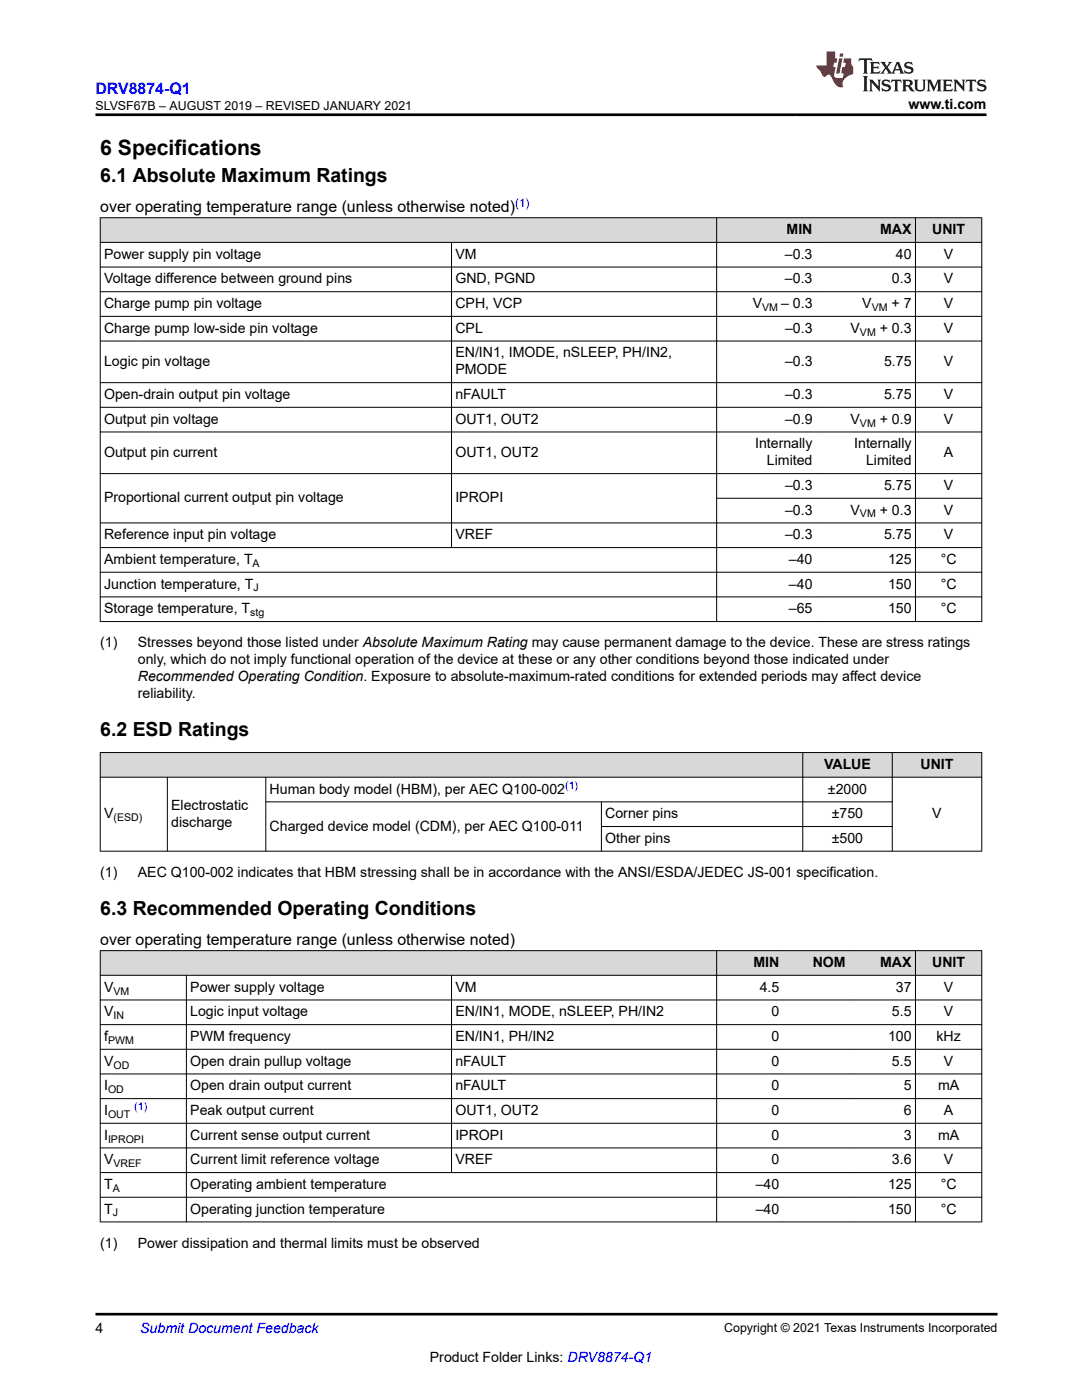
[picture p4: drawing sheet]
<svg xmlns="http://www.w3.org/2000/svg" width="216mm" height="279mm" viewBox="0 0 216 279" stroke-linecap="round" stroke-linejoin="round" font-family="sans-serif">
<defs><g id="words">
<text font-size="4.2" x="20" y="30.9">6 Specifications</text>
<g font-size="3.9">
<text x="20" y="36.3">6.1 Absolute Maximum Ratings</text>
<text x="20" y="146.9">6.2 ESD Ratings</text>
<text x="20" y="182.5">6.3 Recommended Operating Conditions</text>
</g>
<text font-size="3.2" fill="#00f" x="19.1" y="18.7">DRV8874-Q1</text>
<g font-size="3.2">
<text x="20" y="42.4">over operating temperature range (unless otherwise noted)</text>
<text x="20" y="188.7">over operating temperature range (unless otherwise noted)</text>
</g>
<g font-size="2.8">
<text x="181.3" y="21.8">www.ti.com</text>
<text x="157" y="46.7">MIN</text>
<text x="175.6" y="46.7">MAX</text>
<text x="186" y="46.7">UNIT</text>
<text x="20.8" y="51.6">Power supply pin voltage</text>
<text x="90.9" y="51.6">VM</text>
<text x="156.6" y="51.6">–0.3</text>
<text x="178.8" y="51.6">40</text>
<text x="188.3" y="51.6">V</text>
<text x="20.8" y="56.6">Voltage difference between ground pins</text>
<text x="90.9" y="56.6">GND, PGND</text>
<text x="156.6" y="56.6">–0.3</text>
<text x="178" y="56.6">0.3</text>
<text x="188.3" y="56.6">V</text>
<text x="20.8" y="61.5">Charge pump pin voltage</text>
<text x="90.9" y="61.5">CPH, VCP</text>
<text x="150.2" y="61.5">V</text>
<text x="155.9" y="61.5">– 0.3</text>
<text x="172.1" y="61.5">V</text>
<text x="177.9" y="61.5">+ 7</text>
<text x="188.3" y="61.5">V</text>
<text x="20.8" y="66.4">Charge pump low-side pin voltage</text>
<text x="90.9" y="66.4">CPL</text>
<text x="90.9" y="71.3">EN/IN1, IMODE, nSLEEP, PH/IN2,</text>
<text x="156.6" y="66.4">–0.3</text>
<text x="169.7" y="66.4">V</text>
<text x="175.6" y="66.4">+ 0.3</text>
<text x="188.3" y="66.4">V</text>
<text x="20.8" y="73">Logic pin voltage</text>
<text x="90.9" y="74.7">PMODE</text>
<text x="156.6" y="73">–0.3</text>
<text x="176.4" y="73">5.75</text>
<text x="188.3" y="73">V</text>
<text x="20.8" y="79.6">Open-drain output pin voltage</text>
<text x="90.9" y="79.6">nFAULT</text>
<text x="156.6" y="79.6">–0.3</text>
<text x="176.4" y="79.6">5.75</text>
<text x="188.3" y="79.6">V</text>
<text x="20.8" y="84.6">Output pin voltage</text>
<text x="90.9" y="84.6">OUT1, OUT2</text>
<text x="150.7" y="89.5">Internally</text>
<text x="156.6" y="84.6">–0.9</text>
<text x="169.7" y="84.6">V</text>
<text x="170.5" y="89.5">Internally</text>
<text x="175.6" y="84.6">+ 0.9</text>
<text x="188.3" y="84.6">V</text>
<text x="20.8" y="91.2">Output pin current</text>
<text x="90.9" y="91.2">OUT1, OUT2</text>
<text x="153" y="92.9">Limited</text>
<text x="172.8" y="92.9">Limited</text>
<text x="188.3" y="91.2">A</text>
<text x="20.8" y="100.3">Proportional current output pin voltage</text>
<text x="90.9" y="100.3">IPROPI</text>
<text x="156.6" y="97.8">–0.3</text>
<text x="176.4" y="97.8">5.75</text>
<text x="188.3" y="97.8">V</text>
<text x="20.8" y="107.6">Reference input pin voltage</text>
<text x="90.9" y="107.6">VREF</text>
<text x="156.6" y="102.7">–0.3</text>
<text x="156.6" y="107.6">–0.3</text>
<text x="169.7" y="102.7">V</text>
<text x="175.6" y="102.7">+ 0.3</text>
<text x="176.4" y="107.6">5.75</text>
<text x="188.3" y="102.7">V</text>
<text x="188.3" y="107.6">V</text>
<text x="20.8" y="112.6">Ambient temperature, T</text>
<text x="157.4" y="112.6">–40</text>
<text x="177.2" y="112.6">125</text>
<text x="187.7" y="112.6">°C</text>
<text x="20.8" y="117.5">Junction temperature, T</text>
<text x="157.4" y="117.5">–40</text>
<text x="177.2" y="117.5">150</text>
<text x="187.7" y="117.5">°C</text>
<text x="20.8" y="122.4">Storage temperature, T</text>
<text x="157.4" y="122.4">–65</text>
<text x="177.2" y="122.4">150</text>
<text x="187.7" y="122.4">°C</text>
<text x="20" y="129.2">(1)</text>
<text x="27.5" y="129.2">Stresses beyond those listed under Absolute Maximum Rating may cause permanent damage to the device. These are stress ratings</text>
<text x="27.5" y="132.6">only, which do not imply functional operation of the device at these or any other conditions beyond those indicated under</text>
<text x="27.5" y="136">Recommended Operating Condition. Exposure to absolute-maximum-rated conditions for extended periods may affect device</text>
<text x="27.5" y="139.4">reliability.</text>
<text x="164.4" y="153.5">VALUE</text>
<text x="183.7" y="153.5">UNIT</text>
<text x="34.2" y="161.6">Electrostatic</text>
<text x="53.8" y="158.4">Human body model (HBM), per AEC Q100-002</text>
<text x="165.2" y="158.4">±2000</text>
<text x="20.8" y="163.3">V</text>
<text x="34.2" y="165">discharge</text>
<text x="53.8" y="165.8">Charged device model (CDM), per AEC Q100-011</text>
<text x="120.8" y="163.3">Corner pins</text>
<text x="166" y="163.3">±750</text>
<text x="186" y="163.3">V</text>
<text x="120.8" y="168.2">Other pins</text>
<text x="166" y="168.2">±500</text>
<text x="20" y="175">(1)</text>
<text x="27.5" y="175">AEC Q100-002 indicates that HBM stressing shall be in accordance with the ANSI/ESDA/JEDEC JS-001 specification.</text>
<text x="20.8" y="197.9">V</text>
<text x="38" y="197.9">Power supply voltage</text>
<text x="90.9" y="197.9">VM</text>
<text x="150.3" y="193">MIN</text>
<text x="151.6" y="197.9">4.5</text>
<text x="162.2" y="193">NOM</text>
<text x="175.6" y="193">MAX</text>
<text x="178.8" y="197.9">37</text>
<text x="186" y="193">UNIT</text>
<text x="188.3" y="197.9">V</text>
<text x="20.8" y="202.8">V</text>
<text x="38" y="202.8">Logic input voltage</text>
<text x="90.9" y="202.8">EN/IN1, MODE, nSLEEP, PH/IN2</text>
<text x="153.9" y="202.8">0</text>
<text x="178" y="202.8">5.5</text>
<text x="188.3" y="202.8">V</text>
<text x="20.8" y="207.8">f</text>
<text x="38" y="207.8">PWM frequency</text>
<text x="90.9" y="207.8">EN/IN1, PH/IN2</text>
<text x="153.9" y="207.8">0</text>
<text x="177.2" y="207.8">100</text>
<text x="186.9" y="207.8">kHz</text>
<text x="20.8" y="212.7">V</text>
<text x="38" y="212.7">Open drain pullup voltage</text>
<text x="90.9" y="212.7">nFAULT</text>
<text x="153.9" y="212.7">0</text>
<text x="178" y="212.7">5.5</text>
<text x="188.3" y="212.7">V</text>
<text x="20.8" y="217.6">I</text>
<text x="38" y="217.6">Open drain output current</text>
<text x="90.9" y="217.6">nFAULT</text>
<text x="153.9" y="217.6">0</text>
<text x="180.3" y="217.6">5</text>
<text x="187.2" y="217.6">mA</text>
<text x="20.8" y="222.5">I</text>
<text x="20.8" y="227.4">I</text>
<text x="38" y="227.4">Current sense output current</text>
<text x="38" y="222.5">Peak output current</text>
<text x="90.9" y="227.4">IPROPI</text>
<text x="90.9" y="222.5">OUT1, OUT2</text>
<text x="153.9" y="222.5">0</text>
<text x="153.9" y="227.4">0</text>
<text x="180.3" y="222.5">6</text>
<text x="180.3" y="227.4">3</text>
<text x="187.2" y="227.4">mA</text>
<text x="188.3" y="222.5">A</text>
<text x="20.8" y="232.4">V</text>
<text x="38" y="232.4">Current limit reference voltage</text>
<text x="90.9" y="232.4">VREF</text>
<text x="153.9" y="232.4">0</text>
<text x="178" y="232.4">3.6</text>
<text x="188.3" y="232.4">V</text>
<text x="20.8" y="237.3">T</text>
<text x="38" y="237.3">Operating ambient temperature</text>
<text x="150.8" y="237.3">–40</text>
<text x="177.2" y="237.3">125</text>
<text x="187.7" y="237.3">°C</text>
<text x="20.8" y="242.2">T</text>
<text x="38" y="242.2">Operating junction temperature</text>
<text x="150.8" y="242.2">–40</text>
<text x="177.2" y="242.2">150</text>
<text x="187.7" y="242.2">°C</text>
<text x="20" y="249">(1)</text>
<text x="27.5" y="249">Power dissipation and thermal limits must be observed</text>
<text x="19.1" y="266.1">4</text>
<text x="85.8" y="271.7">Product Folder Links: DRV8874-Q1</text>
</g>
<text font-size="2.8" fill="#00f" x="28" y="266.1">Submit Document Feedback</text>
<g font-size="2.5">
<text x="19" y="21.9">SLVSF67B – AUGUST 2019 – REVISED JANUARY 2021</text>
<text x="144.5" y="265.8">Copyright © 2021 Texas Instruments Incorporated</text>
</g>
<text font-size="2.4" fill="#00f" x="102.8" y="41.3">(1)</text>
<g font-size="2.1">
<text x="152.1" y="62.1">VM</text>
<text x="173.9" y="62.1">VM</text>
<text x="171.6" y="67">VM</text>
<text x="171.6" y="85.1">VM</text>
<text x="171.6" y="103.3">VM</text>
<text x="50.4" y="113.1">A</text>
<text x="50.6" y="118">J</text>
<text x="49.9" y="123">stg</text>
<text x="22.6" y="163.9">(ESD)</text>
<text x="22.6" y="203.4">IN</text>
<text x="22.6" y="198.5">VM</text>
<text x="21.6" y="208.3">PWM</text>
<text x="22.6" y="213.2">OD</text>
<text x="21.6" y="218.2">OD</text>
<text x="21.6" y="223.1">OUT</text>
<text x="21.6" y="228">IPROPI</text>
<text x="22.7" y="232.9">VREF</text>
<text x="22.5" y="237.9">A</text>
<text x="22.5" y="242.8">J</text>
</g>
<g font-size="2.1" fill="#00f">
<text x="112.8" y="157.4">(1)</text>
<text x="26.8" y="221.6">(1)</text>
</g>
</g></defs>
<g fill="#d8d8d8">
<path d="M20 43.5h175.9v4.9h-175.9z" fill-rule="evenodd"/>
<path d="M20.1 43.5h122.8v4.8h-122.8z" fill-rule="evenodd"/>
<path d="M143.1 43.5h19.7v4.8h-19.7z" fill-rule="evenodd"/>
<path d="M162.8 43.5h19.8v4.8h-19.8z" fill-rule="evenodd"/>
<path d="M182.7 43.5h13.1v4.8h-13.1z" fill-rule="evenodd"/>
</g>
<g fill="none" stroke="#000" stroke-width=".2">
<path d="M19.9 43.5h176.1M19.9 48.4h176.1M19.9 53.3h176.1M19.9 58.2h176.1M20 43.4v80.7M90.1 48.3v61M143 43.4v80.7M182.7 43.4v80.7M195.9 43.4v80.7M19.9 63.1h176.1M19.9 68.1h176.1M19.9 76.4h176.1"/>
<path d="M19.9 81.3h176.1M19.9 86.2h176.1M19.9 94.5h176.1M142.9 99.4h53.1M19.9 104.4h176.1M19.9 109.3h176.1M19.9 114.2h176.1M19.9 119.1h176.1M19.9 124h176.1"/>
</g>
<g fill="#d8d8d8">
<path d="M20 150.2h175.9v4.9h-175.9z" fill-rule="evenodd"/>
<path d="M20.1 150.2h140v4.8h-140z" fill-rule="evenodd"/>
<path d="M160.2 150.2h17.8v4.8h-17.8z" fill-rule="evenodd"/>
<path d="M178.1 150.2h17.7v4.8h-17.7z" fill-rule="evenodd"/>
</g>
<path d="M19.9 150.2h176.1M19.9 155.1h176.1M20 150.1v19.8M33.4 155v14.9M53 155v14.9M120 160v9.9M160.2 150.1v19.8M178 150.1v19.8M195.9 150.1v19.8M19.9 169.9h176.1M53 160h125.1M119.9 165h58.2" fill="none" stroke="#000" stroke-width=".2"/>
<g fill="#d8d8d8">
<path d="M20 189.7h175.9v4.9h-175.9z" fill-rule="evenodd"/>
<path d="M20.1 189.8h122.8v4.8h-122.8z" fill-rule="evenodd"/>
<path d="M143.1 189.8h13.1v4.8h-13.1z" fill-rule="evenodd"/>
<path d="M156.2 189.8h13.2v4.8h-13.2z" fill-rule="evenodd"/>
<path d="M169.4 189.8h13.2v4.8h-13.2z" fill-rule="evenodd"/>
<path d="M182.7 189.8h13.1v4.8h-13.1z" fill-rule="evenodd"/>
</g>
<g fill="none" stroke="#000" stroke-width=".2">
<path d="M19.9 189.7h176.1M19.9 194.6h176.1M19.9 199.6h176.1M20 189.7v54.2M37.2 194.6v49.3M90.1 194.6v39.5M143 189.7v54.2M182.7 189.7v54.2M195.9 189.7v54.2M19.9 204.5h176.1M19.9 209.4h176.1M19.9 214.3h176.1"/>
<path d="M19.9 219.3h176.1M19.9 224.2h176.1M19.9 229.1h176.1M19.9 234h176.1M19.9 238.9h176.1M19.9 243.9h176.1"/>
</g>
<path d="M171.5 11.6l-.2 .6 .5-.2h.6v.1v2.2l-.2 .4h1l-.2-.4v-2.2v-.1h.5l.6 .2-.2-.6zM173.6 12.4l.2 .3v1.6l-.2 .4h1.9l.1-.6a1.08 1.08 0 0 1-1.3 .2v-.7h.6l.4 .2v-.7l-.4 .2h-.6v-.5l.2-.2a1 1 0 0 1 1 .3l-.1-.5zM175.7 12.4l.9 1.1-1 1.2h.9l-.2-.2 .5-.8 .4 .8-.2 .2h1.6l-.2-.2 .2-.5h.9l.1 .5-.1 .2h.9l-.2-.4-.8-1.9h-.5l-.9 2.1-.9-1.1 .9-1h-.8l.2 .2-.4 .6-.4-.6 .2-.2zM179 12.8l.4 1h-.7zM180.7 12.5a.65 .65 0 0 0-.2 .7 .65 .65 0 0 0 .6 .5l.6 .1 .1 .3a.79 .79 0 0 1-.7 .4 .79 .79 0 0 1-.7-.5l.1 .7 .2-.1a.93 .93 0 0 0 1.1 0 .93 .93 0 0 0 .4-.9 1.46 1.46 0 0 0-1.2-.6l-.1-.3a1.09 1.09 0 0 1 1.2 .2l-.2-.6-.1 .1-.5-.2zM172.2 15.2l.2 .4v2.2l-.2 .4h1l-.2-.4v-2.2l.2-.4zM173.4 15.9l.2 .4v1.5l-.2 .4h.8l-.3-.4 .1-1.3 1.6 1.8v-2l.2-.4h-.7l.1 .2 .1 1.1-1.2-1.3zM176.2 16a.65 .65 0 0 0-.2 .8 .65 .65 0 0 0 .6 .4l.6 .2 .1 .2a.79 .79 0 0 1-.7 .4 .79 .79 0 0 1-.7-.5l.1 .7 .2-.1a.93 .93 0 0 0 1.1 .1 .93 .93 0 0 0 .4-1 1.46 1.46 0 0 0-1.2-.5l-.1-.4a1.09 1.09 0 0 1 1.2 .2l-.1-.6-.2 .1-.5-.1zM177.9 15.9l-.1 .6a.63 .63 0 0 1 .8-.3v1.6l-.3 .4h1l-.2-.4v-1.6a.66 .66 0 0 1 .8 .3l-.1-.6zM180 15.9l.2 .4v1.5l-.2 .4h1l-.2-.2-.1-.7h.5l.1 .2a.79 .79 0 0 0 1.2 .6l-1-.9a.61 .61 0 0 0 .6-.6 .61 .61 0 0 0-.5-.7zM180.8 16.2h.1a.47 .47 0 0 1 .5 .1 .47 .47 0 0 1 .1 .5l-.1 .1-.7 .1zM182.3 15.9l.2 .2a2.27 2.27 0 0 0 .4 2 1.04 1.04 0 0 0 1.7-.7v-1.3l.2-.2h-.8l.2 .4v1.1a.6 .6 0 0 1-.6 .6 .6 .6 0 0 1-.6-.6v-1.1l.3-.4zM184.9 15.9l.2 .4v1.5l-.2 .4h.8l-.3-.4v-1.4l.9 1.9 .9-1.9v1.4l-.3 .4h1l-.2-.4v-1.5l.2-.4h-.8l-.7 1.5-.6-1.5zM188.1 15.9l.2 .4v1.5l-.2 .4h1.9l.1-.6a1.09 1.09 0 0 1-1.3 .2v-.7h.6l.4 .2v-.6l-.4 .2h-.6v-.6l.2-.1a1.01 1.01 0 0 1 1 .3l-.1-.6zM190.2 15.9l.3 .4v1.5l-.3 .4h.8l-.2-.4v-1.3l1.6 1.8v-2l.2-.4h-.7l.2 .2v1.1l-1.2-1.3zM192.8 15.9l-.1 .6a.63 .63 0 0 1 .8-.3v1.6l-.3 .4h1l-.2-.4v-1.6a.66 .66 0 0 1 .8 .3l-.1-.6zM195.2 16a.65 .65 0 0 0-.2 .8 .65 .65 0 0 0 .6 .4l.6 .2 .2 .2a.79 .79 0 0 1-.7 .4 .79 .79 0 0 1-.7-.5l.1 .7 .2-.1a.93 .93 0 0 0 1 .1 .93 .93 0 0 0 .5-1 1.46 1.46 0 0 0-1.3-.5v-.4a1.09 1.09 0 0 1 1.2 .2l-.2-.6-.2 .1-.5-.1z" fill="#231f20"/>
<path d="M164.9 10.3v2.7h-2l.1 .4 .8 1a.95 .95 0 0 0 1 .9 .59 .59 0 0 1 .5-.4 .59 .59 0 0 1 .5 .3l.4 .8a1.59 1.59 0 0 0 2.1 1.4 1.61 1.61 0 0 1 1-2.3l1-.3-.1-1.5a1.59 1.59 0 0 1-.3-1.7h-1.5l-.2 .9h.6l-.2 .9h-.5l-.2 .9v.3l.4 .1-.1 .9h-.7a.73 .73 0 0 1-1-.7l.3-1.5h-.5l.1-.9h.5l.2-.9h-.5v-1.3zM167.4 11.6l-.6 3.1h.7l.6-3.1zM167.6 10.7l-.1 .6h.7l.1-.6z" fill="#ed1c24"/>
<path d="M19.1 22.9h177.8M19.1 262.3h180" fill="none" stroke="#000" stroke-width=".53"/>
<use href="#words"/>
</svg>
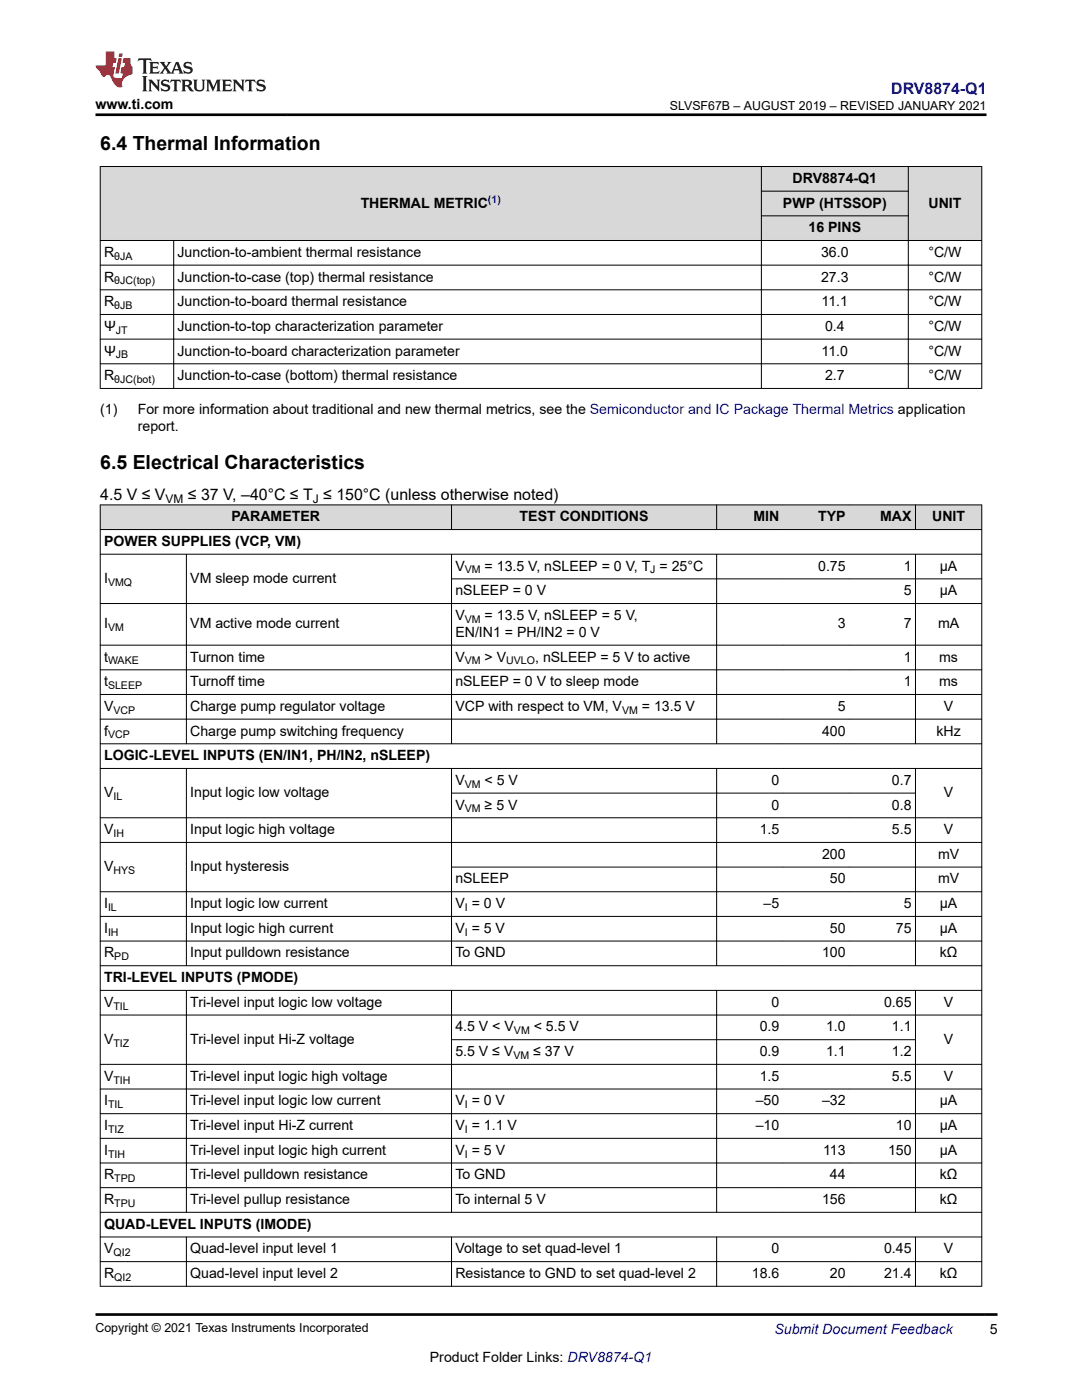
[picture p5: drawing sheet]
<svg xmlns="http://www.w3.org/2000/svg" width="216mm" height="279mm" viewBox="0 0 216 279" stroke-linecap="round" stroke-linejoin="round" font-family="sans-serif">
<defs><g id="words">
<g font-size="3.9">
<text x="20" y="29.9">6.4 Thermal Information</text>
<text x="20" y="93.6">6.5 Electrical Characteristics</text>
</g>
<text font-size="3.2" fill="#00f" x="177.8" y="18.7">DRV8874-Q1</text>
<g font-size="3.2">
<text x="20" y="99.7">4.5 V ≤ V</text>
<text x="37.5" y="99.7">≤ 37 V, –40°C ≤ T ≤ 150°C (unless otherwise noted)</text>
</g>
<g font-size="2.8">
<text x="19.1" y="21.8">www.ti.com</text>
<text x="72" y="41.4">THERMAL METRIC</text>
<text x="156.2" y="41.4">PWP (HTSSOP)</text>
<text x="158.1" y="36.5">DRV8874-Q1</text>
<text x="185.3" y="41.4">UNIT</text>
<text x="161.3" y="46.3">16 PINS</text>
<text x="20.8" y="51.3">R</text>
<text x="35.4" y="51.3">Junction-to-ambient thermal resistance</text>
<text x="163.8" y="51.3">36.0</text>
<text x="185.3" y="51.3">°C/W</text>
<text x="20.8" y="56.2">R</text>
<text x="35.4" y="56.2">Junction-to-case (top) thermal resistance</text>
<text x="163.8" y="56.2">27.3</text>
<text x="185.3" y="56.2">°C/W</text>
<text x="20.8" y="61.1">R</text>
<text x="35.4" y="61.1">Junction-to-board thermal resistance</text>
<text x="163.9" y="61.1">11.1</text>
<text x="185.3" y="61.1">°C/W</text>
<text x="20.8" y="66">Ψ</text>
<text x="20.8" y="71">Ψ</text>
<text x="35.4" y="66">Junction-to-top characterization parameter</text>
<text x="35.4" y="71">Junction-to-board characterization parameter</text>
<text x="163.9" y="71">11.0</text>
<text x="164.6" y="66">0.4</text>
<text x="185.3" y="66">°C/W</text>
<text x="185.3" y="71">°C/W</text>
<text x="20.8" y="75.9">R</text>
<text x="35.4" y="75.9">Junction-to-case (bottom) thermal resistance</text>
<text x="164.6" y="75.9">2.7</text>
<text x="185.3" y="75.9">°C/W</text>
<text x="20" y="82.7">(1)</text>
<text x="27.5" y="82.7">For more information about traditional and new thermal metrics, see the Semiconductor and IC Package Thermal Metrics application</text>
<text x="27.5" y="86.1">report.</text>
<text x="46.2" y="104">PARAMETER</text>
<text x="103.7" y="104">TEST CONDITIONS</text>
<text x="150.3" y="104">MIN</text>
<text x="163.3" y="104">TYP</text>
<text x="175.6" y="104">MAX</text>
<text x="186" y="104">UNIT</text>
<text x="20.8" y="109">POWER SUPPLIES (VCP, VM)</text>
<text x="90.9" y="113.9">V</text>
<text x="96.7" y="113.9">= 13.5 V, nSLEEP = 0 V, T = 25°C</text>
<text x="163.3" y="113.9">0.75</text>
<text x="180.3" y="113.9">1</text>
<text x="187.5" y="113.9">µA</text>
<text x="20.8" y="116.3">I</text>
<text x="38" y="116.3">VM sleep mode current</text>
<text x="90.9" y="118.8">nSLEEP = 0 V</text>
<text x="180.3" y="118.8">5</text>
<text x="187.5" y="118.8">µA</text>
<text x="20.8" y="125.4">I</text>
<text x="38" y="125.4">VM active mode current</text>
<text x="90.9" y="123.7">V</text>
<text x="96.7" y="123.7">= 13.5 V, nSLEEP = 5 V,</text>
<text x="167.2" y="125.4">3</text>
<text x="180.3" y="125.4">7</text>
<text x="187.2" y="125.4">mA</text>
<text x="90.9" y="127.1">EN/IN1 = PH/IN2 = 0 V</text>
<text x="20.8" y="136.9">t</text>
<text x="20.8" y="132">t</text>
<text x="38" y="136.9">Turnoff time</text>
<text x="38" y="132">Turnon time</text>
<text x="90.9" y="136.9">nSLEEP = 0 V to sleep mode</text>
<text x="90.9" y="132">V</text>
<text x="96.7" y="132">&gt; V</text>
<text x="106.8" y="132">, nSLEEP = 5 V to active</text>
<text x="180.3" y="132">1</text>
<text x="180.3" y="136.9">1</text>
<text x="187.4" y="132">ms</text>
<text x="187.4" y="136.9">ms</text>
<text x="20.8" y="141.9">V</text>
<text x="38" y="141.9">Charge pump regulator voltage</text>
<text x="90.9" y="141.9">VCP with respect to VM, V</text>
<text x="128.1" y="141.9">= 13.5 V</text>
<text x="167.2" y="141.9">5</text>
<text x="188.3" y="141.9">V</text>
<text x="20.8" y="146.8">f</text>
<text x="38" y="146.8">Charge pump switching frequency</text>
<text x="164" y="146.8">400</text>
<text x="186.9" y="146.8">kHz</text>
<text x="20.8" y="151.7">LOGIC-LEVEL INPUTS (EN/IN1, PH/IN2, nSLEEP)</text>
<text x="20.8" y="159.1">V</text>
<text x="38" y="159.1">Input logic low voltage</text>
<text x="90.9" y="161.6">V</text>
<text x="90.9" y="156.6">V</text>
<text x="96.7" y="156.6">&lt; 5 V</text>
<text x="96.7" y="161.6">≥ 5 V</text>
<text x="153.9" y="156.6">0</text>
<text x="153.9" y="161.6">0</text>
<text x="178" y="156.6">0.7</text>
<text x="178" y="161.6">0.8</text>
<text x="188.3" y="159.1">V</text>
<text x="20.8" y="166.5">V</text>
<text x="38" y="166.5">Input logic high voltage</text>
<text x="151.6" y="166.5">1.5</text>
<text x="178" y="166.5">5.5</text>
<text x="188.3" y="166.5">V</text>
<text x="20.8" y="173.9">V</text>
<text x="38" y="173.9">Input hysteresis</text>
<text x="164" y="171.4">200</text>
<text x="187.2" y="171.4">mV</text>
<text x="90.9" y="176.3">nSLEEP</text>
<text x="165.6" y="176.3">50</text>
<text x="187.2" y="176.3">mV</text>
<text x="20.8" y="181.2">I</text>
<text x="38" y="181.2">Input logic low current</text>
<text x="90.9" y="181.2">V = 0 V</text>
<text x="152.4" y="181.2">–5</text>
<text x="180.3" y="181.2">5</text>
<text x="187.5" y="181.2">µA</text>
<text x="20.8" y="186.2">I</text>
<text x="20.8" y="191.1">R</text>
<text x="38" y="186.2">Input logic high current</text>
<text x="38" y="191.1">Input pulldown resistance</text>
<text x="90.9" y="186.2">V = 5 V</text>
<text x="90.9" y="191.1">To GND</text>
<text x="164" y="191.1">100</text>
<text x="165.6" y="186.2">50</text>
<text x="178.8" y="186.2">75</text>
<text x="187.5" y="191.1">kΩ</text>
<text x="187.5" y="186.2">µA</text>
<text x="20.8" y="196">TRI-LEVEL INPUTS (PMODE)</text>
<text x="20.8" y="200.9">V</text>
<text x="38" y="200.9">Tri-level input logic low voltage</text>
<text x="153.9" y="200.9">0</text>
<text x="176.4" y="200.9">0.65</text>
<text x="188.3" y="200.9">V</text>
<text x="20.8" y="208.3">V</text>
<text x="38" y="208.3">Tri-level input Hi-Z voltage</text>
<text x="90.9" y="205.8">4.5 V &lt; V</text>
<text x="106.5" y="205.8">&lt; 5.5 V</text>
<text x="151.6" y="205.8">0.9</text>
<text x="164.8" y="205.8">1.0</text>
<text x="178" y="205.8">1.1</text>
<text x="188.3" y="208.3">V</text>
<text x="20.8" y="215.7">V</text>
<text x="38" y="215.7">Tri-level input logic high voltage</text>
<text x="90.9" y="210.8">5.5 V ≤ V</text>
<text x="106.4" y="210.8">≤ 37 V</text>
<text x="151.6" y="215.7">1.5</text>
<text x="151.6" y="210.8">0.9</text>
<text x="164.8" y="210.8">1.1</text>
<text x="178" y="215.7">5.5</text>
<text x="178" y="210.8">1.2</text>
<text x="188.3" y="215.7">V</text>
<text x="20.8" y="220.6">I</text>
<text x="38" y="220.6">Tri-level input logic low current</text>
<text x="90.9" y="220.6">V = 0 V</text>
<text x="150.8" y="220.6">–50</text>
<text x="164" y="220.6">–32</text>
<text x="187.5" y="220.6">µA</text>
<text x="20.8" y="225.5">I</text>
<text x="38" y="225.5">Tri-level input Hi-Z current</text>
<text x="90.9" y="225.5">V = 1.1 V</text>
<text x="150.8" y="225.5">–10</text>
<text x="178.8" y="225.5">10</text>
<text x="187.5" y="225.5">µA</text>
<text x="20.8" y="230.5">I</text>
<text x="38" y="230.5">Tri-level input logic high current</text>
<text x="90.9" y="230.5">V = 5 V</text>
<text x="164.2" y="230.5">113</text>
<text x="177.2" y="230.5">150</text>
<text x="187.5" y="230.5">µA</text>
<text x="20.8" y="235.4">R</text>
<text x="38" y="235.4">Tri-level pulldown resistance</text>
<text x="90.9" y="235.4">To GND</text>
<text x="165.6" y="235.4">44</text>
<text x="187.5" y="235.4">kΩ</text>
<text x="20.8" y="240.3">R</text>
<text x="20.8" y="245.2">QUAD-LEVEL INPUTS (IMODE)</text>
<text x="38" y="240.3">Tri-level pullup resistance</text>
<text x="90.9" y="240.3">To internal 5 V</text>
<text x="164" y="240.3">156</text>
<text x="187.5" y="240.3">kΩ</text>
<text x="20.8" y="250.1">V</text>
<text x="38" y="250.1">Quad-level input level 1</text>
<text x="90.9" y="250.1">Voltage to set quad-level 1</text>
<text x="153.9" y="250.1">0</text>
<text x="176.4" y="250.1">0.45</text>
<text x="188.3" y="250.1">V</text>
<text x="20.8" y="255.1">R</text>
<text x="38" y="255.1">Quad-level input level 2</text>
<text x="90.9" y="255.1">Resistance to GND to set quad-level 2</text>
<text x="150" y="255.1">18.6</text>
<text x="165.6" y="255.1">20</text>
<text x="176.4" y="255.1">21.4</text>
<text x="187.5" y="255.1">kΩ</text>
<text x="197.5" y="266.1">5</text>
<text x="85.8" y="271.7">Product Folder Links: DRV8874-Q1</text>
</g>
<text font-size="2.8" fill="#00f" x="154.5" y="266.2">Submit Document Feedback</text>
<g font-size="2.5">
<text x="133.7" y="21.9">SLVSF67B – AUGUST 2019 – REVISED JANUARY 2021</text>
<text x="19.1" y="265.9">Copyright © 2021 Texas Instruments Incorporated</text>
</g>
<g font-size="2.4">
<text x="33" y="100.3">VM</text>
<text x="62.4" y="100.3">J</text>
</g>
<text font-size="2.1" fill="#00f" x="97.4" y="40.5">(1)</text>
<g font-size="2.1">
<text x="22.8" y="51.8">θJA</text>
<text x="22.8" y="56.8">θJC(top)</text>
<text x="22.8" y="61.7">θJB</text>
<text x="23.1" y="66.6">JT</text>
<text x="23.1" y="71.5">JB</text>
<text x="22.8" y="76.4">θJC(bot)</text>
<text x="21.6" y="116.9">VMQ</text>
<text x="92.7" y="114.4">VM</text>
<text x="129.8" y="114.4">J</text>
<text x="21.6" y="126">VM</text>
<text x="92.7" y="124.3">VM</text>
<text x="21.6" y="137.5">SLEEP</text>
<text x="21.6" y="132.6">WAKE</text>
<text x="92.7" y="132.6">VM</text>
<text x="101" y="132.6">UVLO</text>
<text x="22.6" y="142.4">VCP</text>
<text x="124.1" y="142.4">VM</text>
<text x="21.6" y="147.4">VCP</text>
<text x="22.6" y="159.7">IL</text>
<text x="92.7" y="157.2">VM</text>
<text x="22.6" y="167">IH</text>
<text x="92.7" y="162.1">VM</text>
<text x="22.6" y="174.4">HYS</text>
<text x="21.6" y="181.8">IL</text>
<text x="92.7" y="181.8">I</text>
<text x="21.6" y="186.7">IH</text>
<text x="22.8" y="191.6">PD</text>
<text x="92.7" y="186.7">I</text>
<text x="22.6" y="201.5">TIL</text>
<text x="22.6" y="208.9">TIZ</text>
<text x="102.6" y="206.4">VM</text>
<text x="102.5" y="211.3">VM</text>
<text x="21.6" y="221.2">TIL</text>
<text x="22.6" y="216.3">TIH</text>
<text x="92.7" y="221.2">I</text>
<text x="21.6" y="226.1">TIZ</text>
<text x="92.7" y="226.1">I</text>
<text x="21.6" y="231">TIH</text>
<text x="92.7" y="231">I</text>
<text x="22.8" y="235.9">TPD</text>
<text x="22.8" y="240.9">TPU</text>
<text x="22.6" y="250.7">QI2</text>
<text x="22.8" y="255.6">QI2</text>
</g>
</g></defs>
<g fill="#d8d8d8">
<path d="M20 33.2h175.9v5h-175.9z" fill-rule="evenodd"/>
<path d="M20 38.2h175.9v4.9h-175.9z" fill-rule="evenodd"/>
<path d="M20 43.1h175.9v4.9h-175.9z" fill-rule="evenodd"/>
<path d="M20.1 33.3h131.8v14.6h-131.8z" fill-rule="evenodd"/>
<path d="M152 33.3h29.2v4.8h-29.2z" fill-rule="evenodd"/>
<path d="M181.3 33.3h14.5v14.6h-14.5z" fill-rule="evenodd"/>
<path d="M152 38.2h29.2v4.8h-29.2z" fill-rule="evenodd"/>
<path d="M152 43.1h29.2v4.8h-29.2z" fill-rule="evenodd"/>
</g>
<g fill="none" stroke="#000" stroke-width=".2">
<path d="M19.9 33.2h176.1M20 33.2v44.4M151.9 38.2h29.4M151.9 33.2v44.4M181.2 33.2v44.4M195.9 33.2v44.4M19.9 48h176.1M19.9 52.9h176.1M19.9 57.8h176.1M34.7 47.9v29.7M151.9 43.1h29.4M19.9 62.8h176.1"/>
<path d="M19.9 67.7h176.1M19.9 72.6h176.1M19.9 77.5h176.1"/>
</g>
<g fill="#d8d8d8">
<path d="M20 100.8h175.9v4.9h-175.9z" fill-rule="evenodd"/>
<path d="M20.1 100.8h69.9v4.8h-69.9z" fill-rule="evenodd"/>
<path d="M90.2 100.8h52.7v4.8h-52.7z" fill-rule="evenodd"/>
<path d="M143.1 100.8h13.1v4.8h-13.1z" fill-rule="evenodd"/>
<path d="M156.2 100.8h13.2v4.8h-13.2z" fill-rule="evenodd"/>
<path d="M169.4 100.8h13.2v4.8h-13.2z" fill-rule="evenodd"/>
<path d="M182.7 100.8h13.1v4.8h-13.1z" fill-rule="evenodd"/>
</g>
<g fill="none" stroke="#000" stroke-width=".2">
<path d="M19.9 100.8h176.1M19.9 105.7h176.1M19.9 110.6h176.1M20 100.7v156.1M37.2 110.5v38M90 115.5h106M90.1 110.5v38M90.1 100.7v5M143 100.7v5M143 110.5v38M182.7 100.7v5M182.7 110.5v38"/>
<path d="M195.9 100.7v156.1M19.9 120.4h176.1M19.9 128.8h176.1M19.9 133.7h176.1M19.9 138.6h176.1M19.9 143.5h176.1M19.9 148.4h176.1M19.9 153.4h176.1M37.2 153.3v39.5M90 158.3h92.7M90.1 153.3v39.5M143 153.3v39.5"/>
<path d="M182.7 153.3v39.5M19.9 163.2h176.1M19.9 168.1h176.1M19.9 178h176.1M90 173h106M19.9 182.9h176.1M19.9 187.8h176.1M19.9 192.7h176.1M19.9 197.7h176.1M37.2 197.6v44.4M90.1 197.6v44.4M143 197.6v44.4"/>
<path d="M182.7 197.6v44.4M19.9 202.6h176.1M19.9 212.4h176.1M19.9 217.3h176.1M90 207.5h92.7M19.9 222.3h176.1M19.9 227.2h176.1M19.9 232.1h176.1M19.9 237h176.1M19.9 241.9h176.1M19.9 246.9h176.1M19.9 251.8h176.1"/>
<path d="M19.9 256.7h176.1M37.2 246.8v10M90.1 246.8v10M143 246.8v10M182.7 246.8v10"/>
</g>
<path d="M27.7 11.6l-.2 .6 .5-.2h.6v.1v2.2l-.2 .4h1l-.2-.4v-2.2v-.1h.5l.5 .2-.1-.6zM29.8 12.4l.2 .3v1.6l-.2 .4h1.9l.1-.6a1.08 1.08 0 0 1-1.3 .2v-.7h.6l.4 .2v-.7l-.4 .2h-.6v-.5l.2-.2a1 1 0 0 1 1 .3l-.1-.5zM31.8 12.4l1 1.1-1 1.2h.9l-.2-.2 .4-.8 .5 .8-.2 .2h1.6l-.2-.2 .1-.5h1l.1 .5-.1 .2h.9l-.2-.4-.8-1.9h-.5l-1 2.1-.8-1.1 .9-1h-.8l.2 .2-.5 .6-.3-.6 .1-.2zM35.2 12.8l.4 1h-.8zM36.8 12.5a.65 .65 0 0 0-.2 .7 .65 .65 0 0 0 .6 .5l.7 .1 .1 .3a.79 .79 0 0 1-.7 .4 .79 .79 0 0 1-.7-.5l.1 .7 .2-.1a.93 .93 0 0 0 1.1 0 .93 .93 0 0 0 .4-.9 1.46 1.46 0 0 0-1.2-.6l-.1-.3a1.09 1.09 0 0 1 1.2 .2l-.2-.6-.1 .1-.6-.2zM28.4 15.2l.2 .4v2.2l-.2 .4h1l-.2-.4v-2.2l.2-.4zM29.6 15.9l.2 .4v1.5l-.2 .4h.8l-.3-.4v-1.3l1.7 1.8v-2l.2-.4h-.8l.2 .2 .1 1.1-1.2-1.3zM32.3 16a.65 .65 0 0 0-.2 .8 .65 .65 0 0 0 .7 .4l.6 .2 .1 .2a.79 .79 0 0 1-.7 .4 .79 .79 0 0 1-.7-.5l.1 .7 .2-.1a.93 .93 0 0 0 1.1 .1 .93 .93 0 0 0 .4-1 1.46 1.46 0 0 0-1.2-.5l-.1-.4a1.09 1.09 0 0 1 1.2 .2l-.2-.6-.1 .1-.6-.1zM34.1 15.9l-.1 .6a.63 .63 0 0 1 .7-.3l.1 1.6-.3 .4h1l-.2-.4v-1.6a.66 .66 0 0 1 .8 .3l-.1-.6zM36.2 15.9l.2 .4v1.5l-.2 .4h.9l-.2-.2v-.7h.5l.1 .2a.79 .79 0 0 0 1.2 .6l-1-.9a.61 .61 0 0 0 .6-.6 .61 .61 0 0 0-.5-.7zM36.9 16.2h.2a.47 .47 0 0 1 .5 .1 .47 .47 0 0 1 .1 .5l-.2 .1-.6 .1zM38.5 15.9l.2 .2a2.27 2.27 0 0 0 .4 2 1.04 1.04 0 0 0 1.7-.7v-1.3l.2-.2h-.8l.2 .4v1.1a.6 .6 0 0 1-.6 .6 .6 .6 0 0 1-.6-.6v-1.1l.3-.4zM41.1 15.9l.2 .4v1.5l-.2 .4h.7l-.2-.4v-1.4l.9 1.9 .8-1.9v1.4l-.2 .4h1l-.3-.4v-1.5l.3-.4h-.8l-.7 1.5-.7-1.5zM44.3 15.9l.2 .4v1.5l-.2 .4h1.9l.1-.6a1.09 1.09 0 0 1-1.3 .2v-.7h.6l.4 .2v-.6l-.4 .2h-.6v-.6l.2-.1a1.01 1.01 0 0 1 1 .3l-.1-.6zM46.4 15.9l.3 .4v1.5l-.3 .4h.8l-.2-.4v-1.3l1.6 1.8v-2l.2-.4h-.7l.2 .2v1.1l-1.2-1.3zM49 15.9l-.1 .6a.63 .63 0 0 1 .8-.3v1.6l-.3 .4h1l-.2-.4v-1.6a.66 .66 0 0 1 .8 .3l-.1-.6zM51.4 16a.65 .65 0 0 0-.2 .8 .65 .65 0 0 0 .6 .4l.6 .2 .2 .2a.79 .79 0 0 1-.8 .4 .79 .79 0 0 1-.6-.5l.1 .7 .2-.1a.93 .93 0 0 0 1 .1 .93 .93 0 0 0 .5-1 1.46 1.46 0 0 0-1.3-.5l-.1-.4a1.09 1.09 0 0 1 1.3 .2l-.2-.6-.2 .1-.5-.1z" fill="#231f20"/>
<path d="M21.1 10.3v2.7h-2v.4l.9 1a.95 .95 0 0 0 .9 .9 .59 .59 0 0 1 .6-.4 .59 .59 0 0 1 .5 .3l.4 .8a1.59 1.59 0 0 0 2.1 1.4 1.61 1.61 0 0 1 1-2.3l1-.3-.1-1.5a1.59 1.59 0 0 1-.4-1.7h-1.4l-.2 .9h.5l-.1 .9h-.5l-.2 .9v.3l.4 .1-.2 .9h-.6a.73 .73 0 0 1-1.1-.7l.3-1.5h-.5l.2-.9h.5l.2-.9h-.5v-1.3zM23.6 11.6l-.6 3.1h.7l.6-3.1zM23.8 10.7l-.1 .6h.7l.1-.6z" fill="#ed1c24"/>
<path d="M19.1 22.9h177.8M19.1 262.3h180" fill="none" stroke="#000" stroke-width=".53"/>
<use href="#words"/>
</svg>
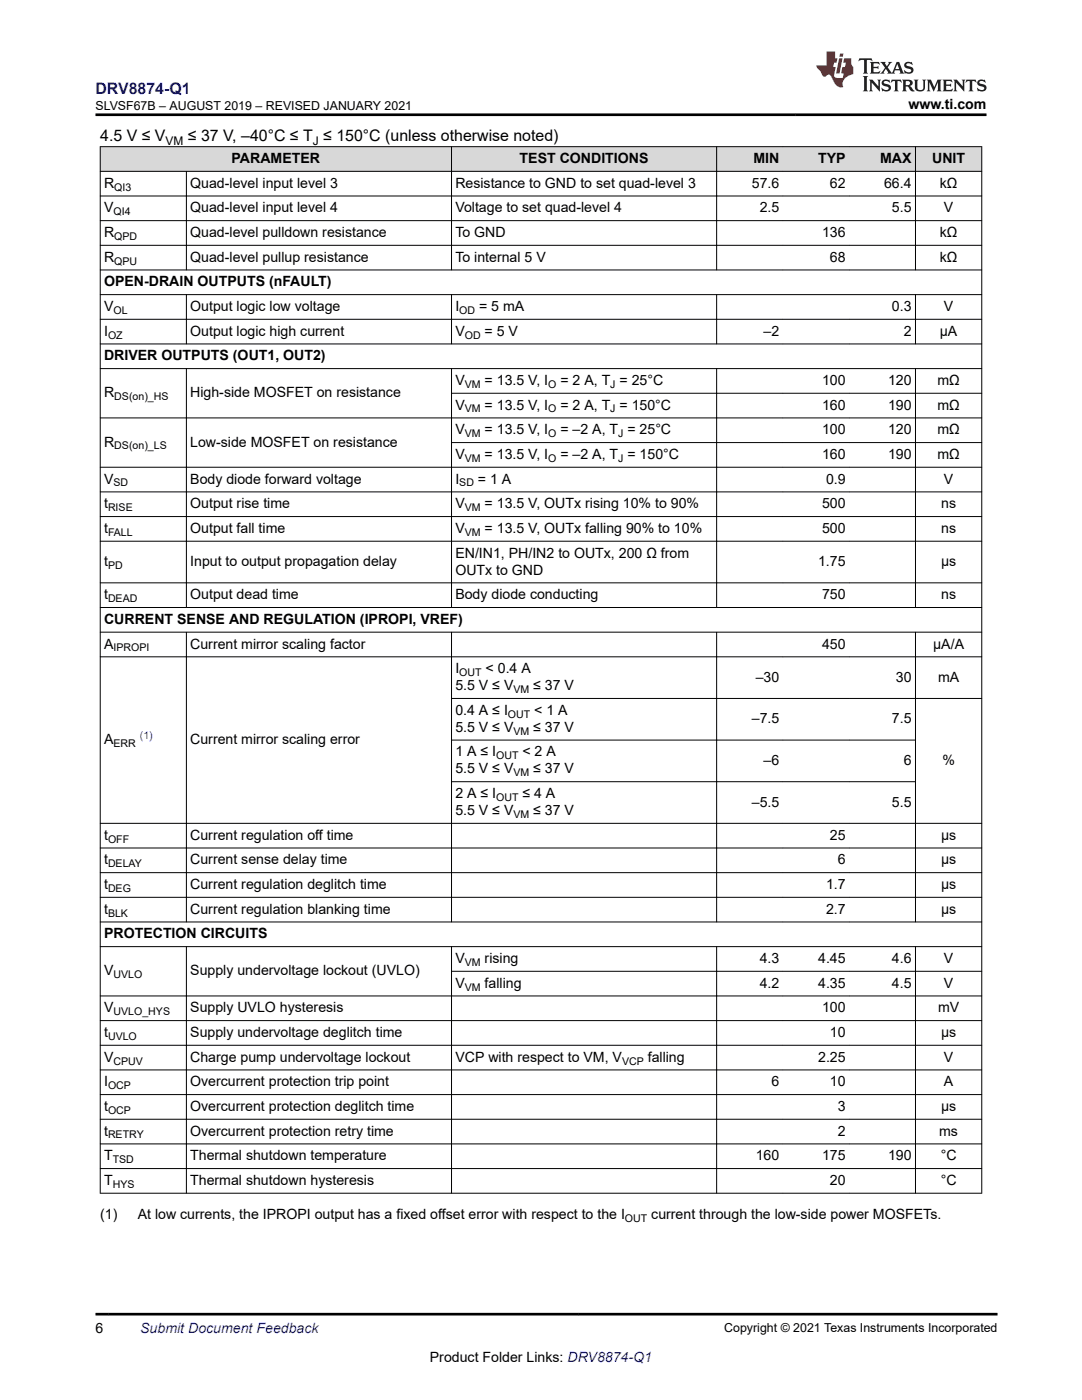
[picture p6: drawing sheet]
<svg xmlns="http://www.w3.org/2000/svg" width="216mm" height="279mm" viewBox="0 0 216 279" stroke-linecap="round" stroke-linejoin="round" font-family="sans-serif">
<defs><g id="words">
<text font-size="3.2" fill="#00f" x="19" y="18.7">DRV8874-Q1</text>
<g font-size="3.2">
<text x="20" y="28.2">4.5 V ≤ V</text>
<text x="37.5" y="28.2">≤ 37 V, –40°C ≤ T ≤ 150°C (unless otherwise noted)</text>
</g>
<g font-size="2.8">
<text x="181.3" y="21.8">www.ti.com</text>
<text x="46.2" y="32.5">PARAMETER</text>
<text x="103.7" y="32.5">TEST CONDITIONS</text>
<text x="150.3" y="32.5">MIN</text>
<text x="163.3" y="32.5">TYP</text>
<text x="175.6" y="32.5">MAX</text>
<text x="186" y="32.5">UNIT</text>
<text x="20.8" y="37.5">R</text>
<text x="38" y="37.5">Quad-level input level 3</text>
<text x="90.9" y="37.5">Resistance to GND to set quad-level 3</text>
<text x="150" y="37.5">57.6</text>
<text x="165.6" y="37.5">62</text>
<text x="176.4" y="37.5">66.4</text>
<text x="187.5" y="37.5">kΩ</text>
<text x="20.8" y="42.4">V</text>
<text x="20.8" y="47.3">R</text>
<text x="38" y="42.4">Quad-level input level 4</text>
<text x="38" y="47.3">Quad-level pulldown resistance</text>
<text x="90.9" y="42.4">Voltage to set quad-level 4</text>
<text x="90.9" y="47.3">To GND</text>
<text x="151.6" y="42.4">2.5</text>
<text x="164" y="47.3">136</text>
<text x="178" y="42.4">5.5</text>
<text x="187.5" y="47.3">kΩ</text>
<text x="188.3" y="42.4">V</text>
<text x="20.8" y="52.2">R</text>
<text x="38" y="52.2">Quad-level pullup resistance</text>
<text x="90.9" y="52.2">To internal 5 V</text>
<text x="165.6" y="52.2">68</text>
<text x="187.5" y="52.2">kΩ</text>
<text x="20.8" y="57.2">OPEN-DRAIN OUTPUTS (nFAULT)</text>
<text x="20.8" y="62.1">V</text>
<text x="38" y="62.1">Output logic low voltage</text>
<text x="90.9" y="62.1">I</text>
<text x="95.6" y="62.1">= 5 mA</text>
<text x="178" y="62.1">0.3</text>
<text x="188.3" y="62.1">V</text>
<text x="20.8" y="71.9">DRIVER OUTPUTS (OUT1, OUT2)</text>
<text x="20.8" y="67">I</text>
<text x="38" y="67">Output logic high current</text>
<text x="90.9" y="67">V</text>
<text x="96.7" y="67">= 5 V</text>
<text x="152.4" y="67">–2</text>
<text x="180.3" y="67">2</text>
<text x="187.5" y="67">µA</text>
<text x="90.9" y="76.8">V</text>
<text x="96.7" y="76.8">= 13.5 V, I</text>
<text x="111.8" y="76.8">= 2 A, T = 25°C</text>
<text x="164" y="76.8">100</text>
<text x="177.2" y="76.8">120</text>
<text x="187.1" y="76.8">mΩ</text>
<text x="20.8" y="79.3">R</text>
<text x="38" y="79.3">High-side MOSFET on resistance</text>
<text x="90.9" y="81.8">V</text>
<text x="96.7" y="81.8">= 13.5 V, I</text>
<text x="111.8" y="81.8">= 2 A, T = 150°C</text>
<text x="164" y="81.8">160</text>
<text x="177.2" y="81.8">190</text>
<text x="187.1" y="81.8">mΩ</text>
<text x="20.8" y="89.1">R</text>
<text x="38" y="89.1">Low-side MOSFET on resistance</text>
<text x="90.9" y="86.7">V</text>
<text x="96.7" y="86.7">= 13.5 V, I</text>
<text x="111.8" y="86.7">= –2 A, T = 25°C</text>
<text x="164" y="86.7">100</text>
<text x="177.2" y="86.7">120</text>
<text x="187.1" y="86.7">mΩ</text>
<text x="90.9" y="91.6">V</text>
<text x="96.7" y="91.6">= 13.5 V, I</text>
<text x="111.8" y="91.6">= –2 A, T = 150°C</text>
<text x="164" y="91.6">160</text>
<text x="177.2" y="91.6">190</text>
<text x="187.1" y="91.6">mΩ</text>
<text x="20.8" y="101.4">t</text>
<text x="20.8" y="96.5">V</text>
<text x="38" y="96.5">Body diode forward voltage</text>
<text x="38" y="101.4">Output rise time</text>
<text x="90.9" y="96.5">I</text>
<text x="90.9" y="101.4">V</text>
<text x="95.4" y="96.5">= 1 A</text>
<text x="96.7" y="101.4">= 13.5 V, OUTx rising 10% to 90%</text>
<text x="164" y="101.4">500</text>
<text x="164.8" y="96.5">0.9</text>
<text x="187.8" y="101.4">ns</text>
<text x="188.3" y="96.5">V</text>
<text x="20.8" y="106.4">t</text>
<text x="38" y="106.4">Output fall time</text>
<text x="90.9" y="106.4">V</text>
<text x="96.7" y="106.4">= 13.5 V, OUTx falling 90% to 10%</text>
<text x="164" y="106.4">500</text>
<text x="187.8" y="106.4">ns</text>
<text x="20.8" y="113">t</text>
<text x="38" y="113">Input to output propagation delay</text>
<text x="90.9" y="111.3">EN/IN1, PH/IN2 to OUTx, 200 Ω from</text>
<text x="163.2" y="113">1.75</text>
<text x="187.8" y="113">µs</text>
<text x="20.8" y="119.6">t</text>
<text x="38" y="119.6">Output dead time</text>
<text x="90.9" y="119.6">Body diode conducting</text>
<text x="90.9" y="114.7">OUTx to GND</text>
<text x="164" y="119.6">750</text>
<text x="187.8" y="119.6">ns</text>
<text x="20.8" y="124.5">CURRENT SENSE AND REGULATION (IPROPI, VREF)</text>
<text x="20.8" y="129.4">A</text>
<text x="38" y="129.4">Current mirror scaling factor</text>
<text x="164" y="129.4">450</text>
<text x="186.2" y="129.4">µA/A</text>
<text x="90.9" y="134.4">I</text>
<text x="90.9" y="137.7">5.5 V ≤ V</text>
<text x="96.9" y="134.4">&lt; 0.4 A</text>
<text x="106.4" y="137.7">≤ 37 V</text>
<text x="150.8" y="136.1">–30</text>
<text x="178.8" y="136.1">30</text>
<text x="187.2" y="136.1">mA</text>
<text x="90.9" y="142.7">0.4 A ≤ I</text>
<text x="106.6" y="142.7">&lt; 1 A</text>
<text x="20.8" y="148.5">A</text>
<text x="38" y="148.5">Current mirror scaling error</text>
<text x="90.9" y="146.1">5.5 V ≤ V</text>
<text x="106.4" y="146.1">≤ 37 V</text>
<text x="150" y="144.4">–7.5</text>
<text x="178" y="144.4">7.5</text>
<text x="90.9" y="154.4">5.5 V ≤ V</text>
<text x="90.9" y="151">1 A ≤ I</text>
<text x="104.3" y="151">&lt; 2 A</text>
<text x="106.4" y="154.4">≤ 37 V</text>
<text x="152.4" y="152.7">–6</text>
<text x="180.3" y="152.7">6</text>
<text x="188" y="152.7">%</text>
<text x="90.9" y="159.3">2 A ≤ I</text>
<text x="104.3" y="159.3">≤ 4 A</text>
<text x="150" y="161">–5.5</text>
<text x="178" y="161">5.5</text>
<text x="20.8" y="167.6">t</text>
<text x="38" y="167.6">Current regulation off time</text>
<text x="90.9" y="162.7">5.5 V ≤ V</text>
<text x="106.4" y="162.7">≤ 37 V</text>
<text x="165.6" y="167.6">25</text>
<text x="187.8" y="167.6">µs</text>
<text x="20.8" y="172.5">t</text>
<text x="38" y="172.5">Current sense delay time</text>
<text x="167.2" y="172.5">6</text>
<text x="187.8" y="172.5">µs</text>
<text x="20.8" y="177.4">t</text>
<text x="38" y="177.4">Current regulation deglitch time</text>
<text x="164.8" y="177.4">1.7</text>
<text x="187.8" y="177.4">µs</text>
<text x="20.8" y="182.4">t</text>
<text x="38" y="182.4">Current regulation blanking time</text>
<text x="164.8" y="182.4">2.7</text>
<text x="187.8" y="182.4">µs</text>
<text x="20.8" y="187.3">PROTECTION CIRCUITS</text>
<text x="20.8" y="194.7">V</text>
<text x="38" y="194.7">Supply undervoltage lockout (UVLO)</text>
<text x="90.9" y="197.1">V</text>
<text x="90.9" y="192.2">V</text>
<text x="96.7" y="192.2">rising</text>
<text x="96.7" y="197.1">falling</text>
<text x="151.6" y="192.2">4.3</text>
<text x="151.6" y="197.1">4.2</text>
<text x="163.2" y="192.2">4.45</text>
<text x="163.2" y="197.1">4.35</text>
<text x="178" y="192.2">4.6</text>
<text x="178" y="197.1">4.5</text>
<text x="188.3" y="192.2">V</text>
<text x="188.3" y="197.1">V</text>
<text x="20.8" y="202">V</text>
<text x="38" y="202">Supply UVLO hysteresis</text>
<text x="164" y="202">100</text>
<text x="187.2" y="202">mV</text>
<text x="20.8" y="207">t</text>
<text x="38" y="207">Supply undervoltage deglitch time</text>
<text x="165.6" y="207">10</text>
<text x="187.8" y="207">µs</text>
<text x="20.8" y="211.9">V</text>
<text x="38" y="211.9">Charge pump undervoltage lockout</text>
<text x="90.9" y="211.9">VCP with respect to VM, V</text>
<text x="129.2" y="211.9">falling</text>
<text x="163.2" y="211.9">2.25</text>
<text x="188.3" y="211.9">V</text>
<text x="20.8" y="216.8">I</text>
<text x="20.8" y="221.7">t</text>
<text x="38" y="216.8">Overcurrent protection trip point</text>
<text x="38" y="221.7">Overcurrent protection deglitch time</text>
<text x="153.9" y="216.8">6</text>
<text x="165.6" y="216.8">10</text>
<text x="167.2" y="221.7">3</text>
<text x="187.8" y="221.7">µs</text>
<text x="188.3" y="216.8">A</text>
<text x="20.8" y="226.6">t</text>
<text x="38" y="226.6">Overcurrent protection retry time</text>
<text x="167.2" y="226.6">2</text>
<text x="187.4" y="226.6">ms</text>
<text x="20.8" y="231.6">T</text>
<text x="38" y="231.6">Thermal shutdown temperature</text>
<text x="150.8" y="231.6">160</text>
<text x="164" y="231.6">175</text>
<text x="177.2" y="231.6">190</text>
<text x="187.7" y="231.6">°C</text>
<text x="20.8" y="236.5">T</text>
<text x="38" y="236.5">Thermal shutdown hysteresis</text>
<text x="165.6" y="236.5">20</text>
<text x="187.7" y="236.5">°C</text>
<text x="20" y="243.3">(1)</text>
<text x="27.5" y="243.3">At low currents, the IPROPI output has a fixed offset error with respect to the I</text>
<text x="130" y="243.3">current through the low-side power MOSFETs.</text>
<text x="19" y="266.1">6</text>
<text x="85.8" y="271.7">Product Folder Links: DRV8874-Q1</text>
</g>
<text font-size="2.8" fill="#00f" x="28" y="266.1">Submit Document Feedback</text>
<g font-size="2.5">
<text x="19" y="21.9">SLVSF67B – AUGUST 2019 – REVISED JANUARY 2021</text>
<text x="144.5" y="265.8">Copyright © 2021 Texas Instruments Incorporated</text>
</g>
<g font-size="2.4">
<text x="33" y="28.9">VM</text>
<text x="62.4" y="28.9">J</text>
</g>
<g font-size="2.1">
<text x="22.8" y="38">QI3</text>
<text x="22.6" y="43">QI4</text>
<text x="22.8" y="47.9">QPD</text>
<text x="22.8" y="52.8">QPU</text>
<text x="22.6" y="62.6">OL</text>
<text x="91.6" y="62.6">OD</text>
<text x="21.6" y="67.6">OZ</text>
<text x="92.7" y="67.6">OD</text>
<text x="92.7" y="77.4">VM</text>
<text x="109.4" y="77.4">O</text>
<text x="121.8" y="77.4">J</text>
<text x="22.8" y="79.9">DS(on)_HS</text>
<text x="92.7" y="82.3">VM</text>
<text x="109.4" y="82.3">O</text>
<text x="121.8" y="82.3">J</text>
<text x="22.8" y="89.7">DS(on)_LS</text>
<text x="92.7" y="87.2">VM</text>
<text x="109.4" y="87.2">O</text>
<text x="123.3" y="87.2">J</text>
<text x="92.7" y="92.2">VM</text>
<text x="109.4" y="92.2">O</text>
<text x="123.3" y="92.2">J</text>
<text x="22.7" y="97.1">SD</text>
<text x="91.6" y="97.1">SD</text>
<text x="21.6" y="102">RISE</text>
<text x="21.6" y="106.9">FALL</text>
<text x="92.7" y="106.9">VM</text>
<text x="92.7" y="102">VM</text>
<text x="21.6" y="113.5">PD</text>
<text x="21.6" y="120.2">DEAD</text>
<text x="22.7" y="130">IPROPI</text>
<text x="91.6" y="134.9">OUT</text>
<text x="101.4" y="143.2">OUT</text>
<text x="102.5" y="138.3">VM</text>
<text x="22.6" y="149.1">ERR</text>
<text x="102.5" y="146.6">VM</text>
<text x="99" y="151.5">OUT</text>
<text x="102.5" y="154.9">VM</text>
<text x="99" y="159.8">OUT</text>
<text x="102.5" y="163.2">VM</text>
<text x="21.6" y="168.2">OFF</text>
<text x="21.6" y="173.1">DELAY</text>
<text x="21.6" y="178">DEG</text>
<text x="21.6" y="182.9">BLK</text>
<text x="22.7" y="195.2">UVLO</text>
<text x="92.7" y="192.8">VM</text>
<text x="92.7" y="197.7">VM</text>
<text x="22.6" y="202.6">UVLO_HYS</text>
<text x="21.6" y="207.5">UVLO</text>
<text x="22.7" y="212.4">CPUV</text>
<text x="124.1" y="212.4">VCP</text>
<text x="21.6" y="217.4">OCP</text>
<text x="21.6" y="227.2">RETRY</text>
<text x="21.6" y="222.3">OCP</text>
<text x="22.5" y="232.1">TSD</text>
<text x="22.5" y="237.1">HYS</text>
<text x="124.7" y="243.9">OUT</text>
</g>
<text font-size="2.1" fill="#00f" x="27.9" y="147.6">(1)</text>
</g></defs>
<g fill="#d8d8d8">
<path d="M20 29.3h175.9v4.9h-175.9z" fill-rule="evenodd"/>
<path d="M20.1 29.3h69.9v4.8h-69.9z" fill-rule="evenodd"/>
<path d="M90.2 29.3h52.7v4.8h-52.7z" fill-rule="evenodd"/>
<path d="M143.1 29.3h13.1v4.8h-13.1z" fill-rule="evenodd"/>
<path d="M156.2 29.3h13.2v4.8h-13.2z" fill-rule="evenodd"/>
<path d="M169.4 29.3h13.2v4.8h-13.2z" fill-rule="evenodd"/>
<path d="M182.7 29.3h13.1v4.8h-13.1z" fill-rule="evenodd"/>
</g>
<g fill="none" stroke="#000" stroke-width=".2">
<path d="M19.9 29.3h176.1M19.9 34.2h176.1M19.9 39.1h176.1M20 29.2v209M37.2 34.1v19.8M90.1 29.2v24.7M143 29.2v24.7M182.7 29.2v24.7M195.9 29.2v209M19.9 44h176.1M19.9 49h176.1M19.9 53.9h176.1"/>
<path d="M19.9 58.8h176.1M37.2 58.7v10M90.1 58.7v10M143 58.7v10M182.7 58.7v10M19.9 63.7h176.1M19.9 68.6h176.1M19.9 73.6h176.1M37.2 73.5v47.8M90 78.5h106M90.1 73.5v47.8M143 73.5v47.8"/>
<path d="M182.7 73.5v47.8M19.9 93.2h176.1M19.9 98.2h176.1M90 88.3h106M196 83.4h-176.1M19.9 103.1h176.1M19.9 108h176.1M19.9 116.3h176.1M19.9 121.2h176.1M19.9 126.2h176.1M19.9 131.1h176.1M37.2 126.1v58"/>
<path d="M90 139.4h106M90.1 126.1v58M143 126.1v58M182.7 126.1v58M90 147.7h92.7M90 156h92.7M19.9 164.3h176.1M19.9 169.2h176.1M19.9 174.2h176.1M19.9 179.1h176.1M19.9 184h176.1M19.9 188.9h176.1"/>
<path d="M19.9 198.8h176.1M37.2 188.9v49.3M90 193.8h106M90.1 188.9v49.3M143 188.9v49.3M182.7 188.9v49.3M19.9 203.7h176.1M19.9 208.6h176.1M19.9 213.5h176.1M19.9 218.4h176.1M19.9 223.4h176.1M19.9 228.3h176.1"/>
<path d="M19.9 233.2h176.1M19.9 238.1h176.1"/>
</g>
<path d="M171.5 11.6l-.2 .6 .5-.2h.6v.1v2.2l-.2 .4h1l-.2-.4v-2.2v-.1h.5l.6 .2-.2-.6zM173.6 12.4l.2 .3v1.6l-.2 .4h1.9l.1-.6a1.08 1.08 0 0 1-1.3 .2v-.7h.6l.4 .2v-.7l-.4 .2h-.6v-.5l.2-.2a1 1 0 0 1 1 .3l-.1-.5zM175.7 12.4l.9 1.1-1 1.2h.9l-.2-.2 .5-.8 .4 .8-.2 .2h1.6l-.2-.2 .2-.5h.9l.1 .5-.1 .2h.9l-.2-.4-.8-1.9h-.5l-.9 2.1-.9-1.1 .9-1h-.8l.2 .2-.4 .6-.4-.6 .2-.2zM179 12.8l.4 1h-.7zM180.7 12.5a.65 .65 0 0 0-.2 .7 .65 .65 0 0 0 .6 .5l.6 .1 .1 .3a.79 .79 0 0 1-.7 .4 .79 .79 0 0 1-.7-.5l.1 .7 .2-.1a.93 .93 0 0 0 1.1 0 .93 .93 0 0 0 .4-.9 1.46 1.46 0 0 0-1.2-.6l-.1-.3a1.09 1.09 0 0 1 1.2 .2l-.2-.6-.1 .1-.5-.2zM172.2 15.2l.2 .4v2.2l-.2 .4h1l-.2-.4v-2.2l.2-.4zM173.4 15.9l.2 .4v1.5l-.2 .4h.8l-.3-.4 .1-1.3 1.6 1.8v-2l.2-.4h-.7l.1 .2 .1 1.1-1.2-1.3zM176.2 16a.65 .65 0 0 0-.2 .8 .65 .65 0 0 0 .6 .4l.6 .2 .1 .2a.79 .79 0 0 1-.7 .4 .79 .79 0 0 1-.7-.5l.1 .7 .2-.1a.93 .93 0 0 0 1.1 .1 .93 .93 0 0 0 .4-1 1.46 1.46 0 0 0-1.2-.5l-.1-.4a1.09 1.09 0 0 1 1.2 .2l-.1-.6-.2 .1-.5-.1zM177.9 15.9l-.1 .6a.63 .63 0 0 1 .8-.3v1.6l-.3 .4h1l-.2-.4v-1.6a.66 .66 0 0 1 .8 .3l-.1-.6zM180 15.9l.2 .4v1.5l-.2 .4h1l-.2-.2-.1-.7h.5l.1 .2a.79 .79 0 0 0 1.2 .6l-1-.9a.61 .61 0 0 0 .6-.6 .61 .61 0 0 0-.5-.7zM180.8 16.2h.1a.47 .47 0 0 1 .5 .1 .47 .47 0 0 1 .1 .5l-.1 .1-.7 .1zM182.3 15.9l.2 .2a2.27 2.27 0 0 0 .4 2 1.04 1.04 0 0 0 1.7-.7v-1.3l.2-.2h-.8l.2 .4v1.1a.6 .6 0 0 1-.6 .6 .6 .6 0 0 1-.6-.6v-1.1l.3-.4zM184.9 15.9l.2 .4v1.5l-.2 .4h.8l-.3-.4v-1.4l.9 1.9 .9-1.9v1.4l-.3 .4h1l-.2-.4v-1.5l.2-.4h-.8l-.7 1.5-.6-1.5zM188.1 15.9l.2 .4v1.5l-.2 .4h1.9l.1-.6a1.09 1.09 0 0 1-1.3 .2v-.7h.6l.4 .2v-.6l-.4 .2h-.6v-.6l.2-.1a1.01 1.01 0 0 1 1 .3l-.1-.6zM190.2 15.9l.3 .4v1.5l-.3 .4h.8l-.2-.4v-1.3l1.6 1.8v-2l.2-.4h-.7l.2 .2v1.1l-1.2-1.3zM192.8 15.9l-.1 .6a.63 .63 0 0 1 .8-.3v1.6l-.3 .4h1l-.2-.4v-1.6a.66 .66 0 0 1 .8 .3l-.1-.6zM195.2 16a.65 .65 0 0 0-.2 .8 .65 .65 0 0 0 .6 .4l.6 .2 .2 .2a.79 .79 0 0 1-.7 .4 .79 .79 0 0 1-.7-.5l.1 .7 .2-.1a.93 .93 0 0 0 1 .1 .93 .93 0 0 0 .5-1 1.46 1.46 0 0 0-1.3-.5v-.4a1.09 1.09 0 0 1 1.2 .2l-.2-.6-.2 .1-.5-.1z" fill="#231f20"/>
<path d="M164.9 10.3v2.7h-2l.1 .4 .8 1a.95 .95 0 0 0 1 .9 .59 .59 0 0 1 .5-.4 .59 .59 0 0 1 .5 .3l.4 .8a1.59 1.59 0 0 0 2.1 1.4 1.61 1.61 0 0 1 1-2.3l1-.3-.1-1.5a1.59 1.59 0 0 1-.3-1.7h-1.5l-.2 .9h.6l-.2 .9h-.5l-.2 .9v.3l.4 .1-.1 .9h-.7a.73 .73 0 0 1-1-.7l.3-1.5h-.5l.1-.9h.5l.2-.9h-.5v-1.3zM167.4 11.6l-.6 3.1h.7l.6-3.1zM167.6 10.7l-.1 .6h.7l.1-.6z" fill="#ed1c24"/>
<path d="M19 22.9h177.8M19 262.3h180" fill="none" stroke="#000" stroke-width=".53"/>
<use href="#words"/>
</svg>
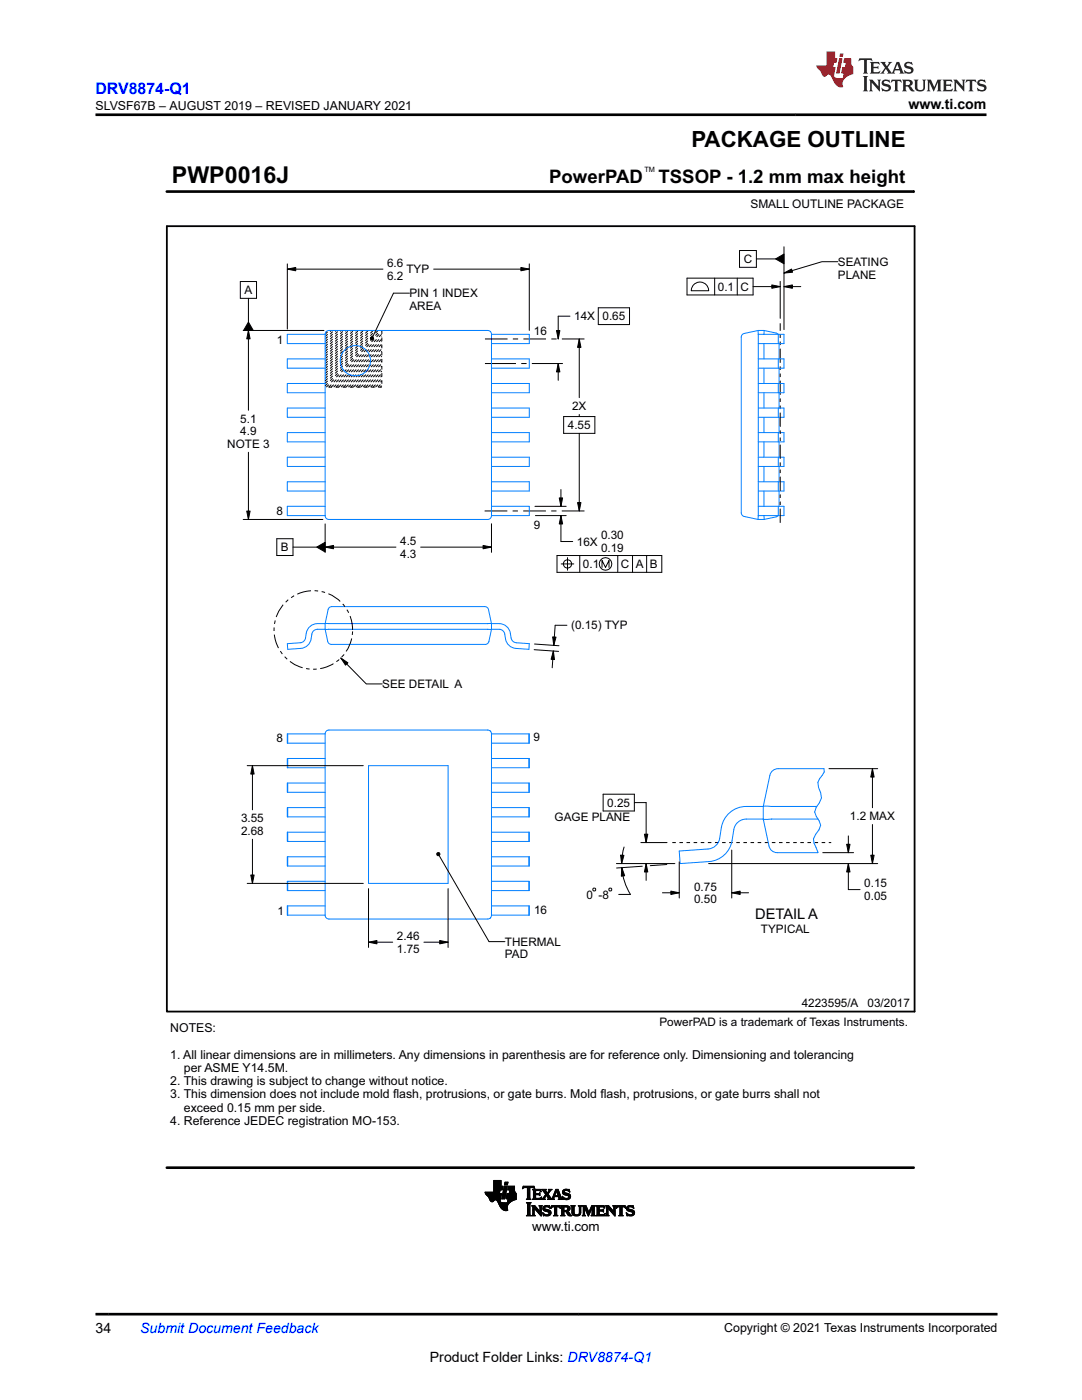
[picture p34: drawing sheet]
<svg xmlns="http://www.w3.org/2000/svg" width="216mm" height="279mm" viewBox="0 0 216 279" stroke-linecap="round" stroke-linejoin="round" font-family="sans-serif">
<defs><g id="words">
<text font-size="4.6" x="34.3" y="36.6">PWP0016J</text>
<text font-size="4.5" x="138" y="29.4">PACKAGE OUTLINE</text>
<g font-size="3.7">
<text x="109.6" y="36.6">PowerPAD</text>
<text x="131.4" y="36.6">TSSOP - 1.2 mm max height</text>
</g>
<text font-size="3.2" fill="#00f" x="19" y="18.7">DRV8874-Q1</text>
<text font-size="2.9" x="150.7" y="183.5">DETAIL A</text>
<g font-size="2.8">
<text x="181.3" y="21.8">www.ti.com</text>
<text x="19" y="266.1">34</text>
<text x="85.8" y="271.7">Product Folder Links: DRV8874-Q1</text>
</g>
<text font-size="2.8" fill="#00f" x="28" y="266.1">Submit Document Feedback</text>
<text font-size="2.7" x="106.2" y="245.6">www.ti.com</text>
<g font-size="2.5">
<text x="19" y="21.9">SLVSF67B – AUGUST 2019 – REVISED JANUARY 2021</text>
<text x="34" y="206">NOTES:</text>
<text x="34" y="211.3">1. All linear dimensions are in millimeters. Any dimensions in parenthesis are for reference only. Dimensioning and tolerancing</text>
<text x="36.7" y="213.9">per ASME Y14.5M.</text>
<text x="34" y="216.6">2. This drawing is subject to change without notice.</text>
<text x="34" y="219.2">3. This dimension does not include mold f</text>
<text x="36.7" y="221.9">exceed 0.15 mm per side.</text>
<text x="78.4" y="219.2">lash, protrusions, or gate burrs. Mold f</text>
<text x="119.8" y="219.2">lash, protrusions, or gate burrs shall not</text>
<text x="34" y="224.5">4. Reference JEDEC registration MO-153.</text>
<text x="144.5" y="265.8">Copyright © 2021 Texas Instruments Incorporated</text>
</g>
<text font-size="2.4" x="149.7" y="41.6">SMALL OUTLINE PACKAGE</text>
<g font-size="2.3">
<text x="77.3" y="53.3">6.6</text>
<text x="148.4" y="52.5">C</text>
<text x="167.2" y="53.1">SEATING</text>
<text x="48.8" y="58.7">A</text>
<text x="77.3" y="55.8">6.2</text>
<text x="81.1" y="54.5">TYP</text>
<text x="81.7" y="59.3">PIN 1 INDEX</text>
<text x="143.2" y="58">0.1 C</text>
<text x="167.2" y="55.6">PLANE</text>
<text x="81.7" y="61.9">AREA</text>
<text x="114.6" y="63.9">14X 0.65</text>
<text x="55.2" y="68.6">1</text>
<text x="106.5" y="66.8">16</text>
<text x="114.2" y="81.9">2X</text>
<text x="45.3" y="89.4">NOTE 3</text>
<text x="47.9" y="84.4">5.1</text>
<text x="47.9" y="86.9">4.9</text>
<text x="113.3" y="85.6">4.55</text>
<text x="55.2" y="102.7">8</text>
<text x="106.5" y="105.5">9</text>
<text x="119.9" y="107.7">0.30</text>
<text x="56.1" y="110">B</text>
<text x="79.8" y="108.8">4.5</text>
<text x="79.8" y="111.3">4.3</text>
<text x="115.1" y="108.9">16X</text>
<text x="116.3" y="113.4">0.1</text>
<text x="119.9" y="110.2">0.19</text>
<text x="123.9" y="113.4">C A B</text>
<text x="114" y="125.6">(0.15) TYP</text>
<text x="76.3" y="137.3">SEE DETAIL A</text>
<text x="55.2" y="148.1">8</text>
<text x="106.5" y="147.9">9</text>
<text x="121.2" y="161">0.25</text>
<text x="48.1" y="164.1">3.55</text>
<text x="48.1" y="166.6">2.68</text>
<text x="110.7" y="163.9">GAGE PLANE</text>
<text x="169.6" y="163.7">1.2 MAX</text>
<text x="117" y="179.3">0 -8</text>
<text x="138.5" y="177.8">0.75</text>
<text x="172.5" y="177.1">0.15</text>
<text x="172.5" y="179.6">0.05</text>
<text x="55.4" y="182.6">1</text>
<text x="106.6" y="182.5">16</text>
<text x="138.5" y="180.3">0.50</text>
<text x="79.2" y="187.6">2.46</text>
<text x="79.2" y="190.1">1.75</text>
<text x="100.8" y="188.8">THERMAL</text>
<text x="100.8" y="191.3">PAD</text>
<text x="151.8" y="186.1">TYPICAL</text>
<text x="160" y="201">4223595/A</text>
<text x="173.1" y="201">03/2017</text>
<text x="131.6" y="204.8">PowerPAD is a trademark of Texas Instruments.</text>
</g>
<text font-size="1.5" x="128.6" y="34.3">TM</text>
</g></defs>
<g fill="none" stroke="#000" stroke-width=".2">
<path d="M33.3 38.2h149M182.3 38v.4M48 56.2h3.2v3.3h-3.2zM49.6 59.5v4.8M57.3 53.7l1.7-.3v.6zM57.3 52.7v13M57.3 53.7h19.1M81.7 58.5h-3.2l-4.1 8.7M86.5 53.7h19.1M103.9 53.4l1.7 .3-1.7 .3zM105.6 52.7v13.2M137.1 55.5h13.2v3.4h-13.2z"/>
<path d="M138.3 57a1.75 1.75 0 0 1 1.9-.6 1.75 1.75 0 0 1 1.2 1.6h-3.5zM142.6 55.5v3.4M147.1 55.5v3.4M147.6 50h3.3v3.3h-3.3zM150.3 57.2h5.4M150.9 51.7h3.9M154 56.9l1.7 .3-1.7 .3zM154.8 51.7l1.6-1v1.9zM155.7 56.2v7.3M156.4 54.5l1.5-.8 .2 .6zM156.4 57.2l1.7-.3v.6zM156.4 49.2v16.6"/>
<path d="M156.4 57.2h3.4M167.2 52.2h-3.2l-7.6 2.3M48.5 66h16.1M49.6 66l.3 1.6h-.7zM49.6 66v15.9M49.6 64.3l.9 1.7h-1.9zM73.9 67.4l.2-.2 .3 .1 .2 .2-.2 .3-.3 .1-.2-.2zM96.8 72.6h6.2M96.8 67.6h4.5M102.3 67.6h1.1M104 72.6h1.1M104.4 67.6h4.6"/>
<path d="M106.1 72.6h6.2M110 67.6h1.1M111 66h.7l-.3 1.6zM111.4 72.6l.3 1.6h-.7zM111.4 72.6v3.3M112.1 67.6h4.5M113.7 63.1h-2.3v4.5M115.6 67.6l.3 1.7h-.7zM115.6 67.6v11.8M119.4 61.4h6.2v3.4h-6.2zM49.6 90.3v13.4M111.6 99.4h.7l-.4 1.6z"/>
<path d="M111.9 97.7v3.3M115.6 82.7v.4M115.6 86.5v15.5M118.7 83.1h-6.2v3.4h6.2v-3.4M48.5 103.7h15.9M49.2 102h.7l-.3 1.7zM55.2 107.5h3.3v3.4h-3.3zM58.5 109.2h4.7M63.2 109.2l1.7-1v2zM64.9 109.2l1.7-.3v.6zM64.9 109.2h14.1M64.9 104.6v5.6"/>
<path d="M83.9 109.2h14.2M96.4 108.9l1.7 .3-1.7 .3zM96.7 102h4.5M98.1 104.5v5.7M102.3 102h1M104.4 102h4.5M106.7 101h6.3M106.8 102.9h6.2M110 102h1M111.1 110.9h21v3.3h-21zM111.9 102.9l.4 1.7h-.7zM111.9 102.9v5.2h2.4"/>
<path d="M112 112.5h2.5M112.1 102h4.5M113.2 111.3v2.5M115.2 100.3h.7l-.3 1.7zM115.7 110.9v3.3M120.1 113.2v-1.4l.7 1.4 .7-1.4v1.4M123.3 110.9v3.3M126.2 110.9v3.3M129 110.9v3.3M68 131.3l1.4 1-.5 .4zM68 131.3l5.1 5.2h3.2M106.6 129.7l4.9 .3"/>
<path d="M106.7 128.5l4.8 .4M110.3 127.1h.6l-.4 1.7zM110.4 129.9l.2 1.7h-.6zM110.4 129.9l-.2 3.4M113.1 124.8h-2.3l-.3 4M49.3 152.8h23.2M50.4 152.8l.3 1.7h-.7zM50.4 152.8v8.8M120.3 158.5h6.3v3.4h-6.3zM165.4 153.4h9.7M174.1 153.4l.3 1.7h-.6zM174.1 153.4v7.8"/>
<path d="M49.3 176.3h23.2M50 174.6h.7l-.3 1.7zM50.4 167.5v8.8M73.5 177.4v11.7M87.2 170.3l.2-.2 .3 .1 .1 .3-.1 .2-.3 .1-.2-.2zM87.6 170.7l10 17.2h3.2M89.4 177.4v11.7M118.3 177.4l.4-.2 .2 .5-.5 .1zM121.5 177.4l.4-.2 .2 .5-.5 .1zM123 172.3h11.7M123.8 170.7h.7l-.5 1.6zM124.1 173.2l.5 1.6-.6 .1z"/>
<path d="M124.1 173.2a11.7 11.7 0 0 0 1.7 5.3h-2.3M124.5 169l-.3 1.7-.2 1.6M126.6 160.2h2.3v8M127.9 168.2h5.2M128.2 172.9l-5.2 .3M128.6 166.5h.7l-.4 1.7zM128.9 172.3l.4 1.7h-.7zM128.9 172.3v3.4M132.2 178.2h3.3M133.1 172.5l-3.3 .3M133.9 177.8l1.6 .4-1.6 .3zM135.5 172v7.2"/>
<path d="M141.4 172.3h33.7M146 178.2l1.7-.4v.7zM146 178.2h3.4M146 169.6v9.6M164.2 170.2h6.1M168.9 168.5h.7l-.3 1.7zM169.3 172.3l.3 1.7h-.7zM169.3 172.3v5.2h2.3M169.3 166.8v3.4M173.8 170.7h.6l-.3 1.6zM174.1 164.6v7.7M73.5 188l1.7-.3v.7z"/>
<path d="M73.5 188h4.9M84.6 188h4.8M87.7 187.7l1.7 .3-1.7 .4zM96.8 238h2.9M96.8 238.1h2.9M96.8 238.2h2.9M96.9 238.2h3.2M96.9 238.3h3.1M97 238.4h3M97.1 238.5h2.9M97.1 238.6h2.9M97.2 238.6h2.8"/>
<path d="M97.3 238.7h2.7M97.4 238.8h2.6M97.4 238.8h2.5M97.5 238.9h2.4M97.5 239h2.4M97.6 239h2.3M97.6 239.1h2.3M97.6 239.2h2.3M97.7 239.3h2.1M97.7 239.4h2.1M97.8 239.5h.9M97.8 239.6h.8"/>
<path d="M97.9 239.7h.6M98 239.8h.4M98.1 239.8h.2M98.5 237.8h1.2M98.5 237.7h1.2M98.5 237.6h1.3M98.5 236.8l1.9-.1-.2 .8h-1.7M98.5 237.4h1.7M98.5 237.3h1.7M98.5 237.2h1.8M98.5 237.1h1.8M98.5 237h1.8"/>
<path d="M98.5 236.9h1.8M98.5 236.8h1.8M98.5 236.7h1.5M98.5 236.6h1.5M98.5 236.5h1.5M98.5 236.4h1.5M98.5 236.3h1.5M98.5 236.2h1.5M98.5 236.1h1.5M98.5 236h1.5M98.5 235.9h1.5M98.5 235.8h1.5"/>
<path d="M98.5 235.7h1.5M98.5 235.6h1.5M99 239.5h.8M99.1 239.6h.7M99.2 239.6h.6M99.2 239.7h.6M99.3 239.8h.5M99.4 239.9h.5M99.4 240h.6M99.7 237.9h-2.9l.1 .4 .6 .6 .4 .8 .4 .1 .4-.3h.4l.8 1.5 .7 .6 .7-.1v-.8l.6-.8M99.8 237.5l-.2 .7h.5l-.2 1M99.8 239.5v.3l.3 .2h1.6"/>
<path d="M99.9 239.2l-.1 .3M100 236.7v-1.1h-1.5v2.3M100.1 239.2h.6M100.2 239.1h.5M100.2 239h.6M100.2 238.9h.6M100.2 238.8h.6M100.2 238.7h.6M100.2 238.6h.6M100.3 238.6h.5M100.3 238.5h.6M100.3 238.4h.6"/>
<path d="M100.3 238.3h.6M100.3 238.2h.6M100.4 238.1h.5M100.4 238h.6M100.4 237.9h.6M100.4 237.8h.6M100.4 237.7h.6M100.4 237.6h.6M100.5 237.6h.5M100.5 237.5h.6M100.5 237.4h.6M100.5 237.3h.6"/>
<path d="M100.5 237.2h.6M100.6 237.1h.5M100.6 237h.5M100.6 237h.6M100.6 236.9h.6M100.6 236.8h.6M100.6 236.8l.6-.1-.5 2.6h-.6zM100.7 236.4h.6M100.7 236.3h.6M100.7 236.2h.6M100.7 236.1h.6M100.8 236h.5"/>
<path d="M100.8 236h.6M100.8 235.9h.6l-.1 .6h-.6zM101 239.2h2M101 239.1h2M101 239.1v.2h.4M101 239h2M101 238.9v.2M101 238.9h2M101 238.8h2M101.1 238.8h1.9M101.1 238.7h1.9M101.1 238.6h1.9"/>
<path d="M101.1 238.5h1.9M101.1 238.4h1.9M101.1 238.3h1.9M101.2 238.2h1.8M101.3 240h.5M101.3 239.9h.6M101.3 239.8h.7M101.3 239.8h.8M101.3 239.7h.9M101.3 239.6h1M101.3 237.4h1.4M101.3 239.6h1.2"/>
<path d="M101.3 239.5h1.3M101.3 237.3h1.4M101.4 239.4h1.4M101.4 237.2h1.3M101.4 239.4h1.6M101.4 239.3h1.6M101.4 239.3l-.2 .7M101.4 237.1h1.3M101.4 237h1.3M101.4 236.9h1.3M101.4 236.8h1.3M101.5 236.7l1.2 .1v.7h-1.4z"/>
<path d="M101.6 238.2h1.4M101.6 238.1h1.3M101.6 238h1.3M101.6 238h1.2M101.7 237.9h1.1M101.7 237.8h1M101.7 237.7h1M101.7 237.6h1M101.7 237.5l-.1 .7h-.4l-.2 .7M102.7 237.5l.1 .4 .2 .3v1.2l-1.1 .5M104.3 237.2h.1M104.3 237.1h.2"/>
<path d="M104.3 237h2.3M104.4 236.9h2.2M104.4 236.8h2.2M105 239.3h.9M105.2 239.2h.6M105.2 237.1h.5M105.2 239.1h.5M105.2 237.2v-.2h-.4l-.6 .2 .2-.5h2.1l.2 .5-.5-.2h-.4l-.1 .2M105.2 239.1l-.2 .2M105.2 239h.5M105.2 238.9h.5M105.2 238.8h.5"/>
<path d="M105.2 238.7h.5M105.2 238.6h.5M105.2 238.5h.5M105.2 238.4h.5M105.2 238.3h.5M105.2 238.2h.5M105.2 238.1h.5M105.2 238h.5M105.2 237.9h.5M105.2 237.8h.5M105.2 237.7h.5M105.2 237.6h.5"/>
<path d="M105.2 237.5h.5M105.2 237.4h.5M105.2 237.3h.5M105.2 237.2h.5M105.2 237.2v1.9M105.7 239.1l.2 .2M105.7 237.2v1.9M105.9 239.3h-.9M106.2 239.3h1.7M106.3 237.4h1.6M106.4 239.2h1.6M106.4 237.5h1.5"/>
<path d="M106.4 239.1h.5M106.4 237.6h.5M106.4 239.1l-.2 .2M106.4 238.2h1.1l.2-.2v.6l-.2-.2h-.6v.7h.8l.4-.2-.2 .5-1.7-.1M106.4 239h.5M106.4 238.9h.5M106.4 238.8h.5M106.4 238.7h.5M106.4 238.6h.5M106.4 238.5h.5M106.4 238.4h1.3M106.4 238.3h1.3"/>
<path d="M106.4 238.1h.5M106.4 238h.5M106.4 237.9h.5M106.4 237.8h.5M106.4 237.7h.5M106.5 237.1h.2M106.6 237.2h.1M106.9 237.7l.1-.1h.5l.5 .2M106.9 237.7v.5M107.5 238.2h.2M107.6 238.5h.1M107.6 239.1h.4"/>
<path d="M107.6 238.1h.1M107.6 238.6h.1M107.6 237.6h.3M107.8 237.7h.2M107.9 239h.1M107.9 237.8h.1M108 238.9h.1M108 237.8l-.2-.4h-1.6l.2 .2v1.5M108 239.3h.8M108.1 237.4h.8M108.3 239.2h.3M108.3 237.5h.6"/>
<path d="M108.3 239.1h.4M108.4 237.6h.5M108.4 239.1l-.4 .2M108.4 239h.3M108.4 237.7h.6M108.5 238.9h.3M108.5 237.8h.5M108.6 237.9h.5M108.6 238.8h.3M108.6 238h.5M108.7 238.7h.3M108.7 238.1h.8"/>
<path d="M108.7 238.6h.8M108.8 238.2h.6M108.8 239.3h-.8M108.8 238.5h.7M108.8 238.3h.6M108.9 238.4h.5M108.9 238.4l-.5 .7M109.1 238.7h.5M109.2 238.8h.5M109.2 238.9h.5M109.3 239.3l.1-.1-.4-.6-.3 .6 .1 .1M109.3 239.3h1.3"/>
<path d="M109.3 238h.3M109.3 238.9h.5M109.3 237.9h.3M109.4 238.3l.7 1 .8-1.9h.5l.6 1.7 .3 .2M109.4 239h.5M109.4 237.8h.3M109.4 239.1h.5M109.4 239.2h.6M109.5 237.7h.3M109.5 237.4h.6M109.5 237.6l-.3 .5-.3-.5 .1-.2h-.9l.8 1M109.5 237.6l-.1-.2h.7l-.7 .9"/>
<path d="M109.5 237.6h.3M109.6 237.5h.3M110.1 239.2h.4M110.2 239.1h.3M110.2 239h.3M110.3 238.9h.3M110.3 238.9h1.6M110.4 238.8h1.5M110.4 238.7h1.5M110.4 238.6h.3M110.5 238.5h.2M110.5 238.4h.3"/>
<path d="M110.5 238.3h.3M110.6 238.2h.2M110.6 238.8l-.1 .4 .1 .1M110.6 238.1h.3M110.6 239.3h-1.3M110.7 238h.2M110.7 237.9h.3M110.7 237.8h.3M110.8 237.7h.7M110.8 237.6h.7M110.8 237.5h.6M110.9 237.4h.5"/>
<path d="M111 237.7l.4 .9h-.7zM111.1 237.8h.4M111.1 237.9h.5M111.1 238h.5M111.2 238.1h.4M111.2 238.2h.5M111.2 238.3h.5M111.3 238.4h.5M111.3 238.5h.5M111.3 238.6h.5M111.4 239.3h.9M111.4 238.8l.1 .3"/>
<path d="M111.5 238.9h.5M111.5 239h.5M111.5 239.1l-.1 .2M111.5 239.2h.6M111.5 239.1h.5M112.2 238.9h.1M112.2 238.8h.1M112.2 238.9h.2M112.2 237.9h.4M112.2 238h.5M112.2 237.8h.4M112.2 239h.4"/>
<path d="M112.3 239.3h-.9M112.3 238.1h.7M112.3 237.7h.3M112.3 239.1h.5M112.3 238.2h1.1M112.3 239.2h1.4M112.3 237.6h.4M112.3 239.3h.2M112.4 238.3h1.2M112.4 237.5h1.2M112.5 238.4h1.2M112.5 237.4h1.1"/>
<path d="M112.6 239.3h.9M112.7 238.5h1.1M112.7 237.4h.5M112.9 239.4h.3M113.1 238.6h.7M113.3 239.1h.4M113.3 237.6h.3M113.4 238.7h.5M113.4 239h.4M113.4 238.8h.5M113.5 238.9h.3M113.5 237.7h.2"/>
<path d="M113.5 238.9h.4M113.6 237.8h.1M113.7 237.9l-.6-.3h-.4l-.1 .2 .1 .2 1.1 .4v.5l-.2 .4-1.3 .1-.1-.7M113.7 237.9l-.1-.5h-1.1l-.2 .4v.4l1.1 .5 .1 .2-.2 .2-.4 .1-.7-.5M113.7 237.9h.1M99.4 240h1M99.5 240.1h2.1M99.5 240.2h2.1M99.5 240.2h2M99.5 240.3h2M99.6 240.4h1.8M99.6 240.5h1.7"/>
<path d="M99.7 240.6h1.6M99.7 240.7h1.5M99.8 240.8h1.4M99.8 240.9h1.4M99.9 241h1.3M100 241.1h1.2M100 241.2h1.2M100.1 241.2h1.1M100.2 241.3h1M100.3 241.4h1M100.5 241.5h.8M100.6 241.6h.7"/>
<path d="M100.9 241.6h.1M105 242.6h1M105.1 240.1h.8M105.2 242.5h.6M105.2 240.2h.6M105.3 242.4h.5M105.3 240.3h.4M105.3 242.3h.4M105.3 240.3l-.3-.3h1l-.3 .3M105.3 242.3l-.3 .3M105.3 242.2h.4M105.3 242.1h.4"/>
<path d="M105.3 242h.4M105.3 241.9h.4M105.3 241.8h.4M105.3 241.7h.4M105.3 241.6h.4M105.3 241.5h.4M105.3 241.4h.4M105.3 241.3h.4M105.3 241.2h.4M105.3 241.1h.4M105.3 241h.4M105.3 240.9h.4"/>
<path d="M105.3 240.8h.4M105.3 240.7h.4M105.3 240.6h.4M105.3 240.5h.4M105.3 240.4h.4M105.3 240.3v2M105.7 242.3l.3 .3M105.7 240.3v2M106 242.6h-1M106.1 242.6h.7M106.1 240.6h.6M106.2 240.7h.6"/>
<path d="M106.3 242.5h.4M106.3 240.8h.6M106.3 242.4h.3M106.3 240.9h.7M106.3 240.9l-.2-.3h.6l1 1.2M106.3 242.3l-.2 .3M106.3 242.3h.3M106.3 242.2h.3M106.3 242.1h.3M106.3 242h.3M106.3 241.9h.3M106.3 241.8h.3"/>
<path d="M106.3 241.7h.3M106.3 241.6h.3M106.3 241.5h.3M106.3 241.4h.3M106.3 241.3h.3M106.3 241.2h.3M106.3 241.1h.8M106.3 241h.8M106.3 240.9v1.4M106.6 242.3l.2 .3M106.6 241.1h.1M106.6 241.1v1.2"/>
<path d="M106.7 241.2h.5M106.7 241.3h.6M106.8 242.6h-.7M106.8 241.4h.6M106.9 241.5h.6M107 241.6h.6M107.1 241.7h.5M107.1 241.8h.9M107.2 241.9h.8M107.3 242h.7M107.4 242h.6M107.5 242.1h.5"/>
<path d="M107.6 242.2h.4M107.6 240.6h.6M107.6 242.3h.4M107.7 240.7h.4M107.7 242.4h.3M107.7 240.8h.3M107.7 241.8h.1M107.7 240.9h.3M107.8 240.9l-.2-.3h.6l-.2 .3M107.8 241.7h.2M107.8 241.6h.2M107.8 241.5h.2"/>
<path d="M107.8 241.4h.2M107.8 241.3h.2M107.8 241.2h.2M107.8 241.1h.2M107.8 241h.2M107.8 240.9v.9M107.8 242.5h.2M107.9 242.6h.1M108 240.9v1.8l-1.4-1.6M108.3 242h.1M108.3 242.1h.1M108.3 242.2h.3"/>
<path d="M108.3 241.2h.4M108.3 241.1h.4M108.3 241.3h.5M108.3 242.3h.4M108.3 241h.4M108.4 241.4h.8M108.4 242.4h.6M108.4 240.9h.4M108.4 242.5h1.3M108.4 241.5h1.2M108.4 242.6h.1M108.4 240.8h1.3"/>
<path d="M108.5 241.6h1.2M108.5 240.7h1.2M108.6 241.7h1.2M108.7 242.6h.9M108.7 240.6h.7M108.9 241.8l-.5-.4v-.5l.4-.3h.9l.1 .6-.7-.4-.3 .1-.1 .3 1 .4 .2 .4M108.9 241.8l.6 .1v.4l-.6 .1-.6-.4M108.9 241.8h1M109.2 242.4h.6M109.3 241.9h.6M109.4 240.9h.3M109.5 242.3h.4"/>
<path d="M109.5 242h.4M109.5 242.2h.4M109.6 242.1h.3M109.6 240.6h.1M109.6 241h.2M109.7 241.1h.1M109.9 241.1h.1M109.9 241h.2M109.9 242l-.2 .5-.6 .2-.5-.1h-.2l-.1-.6M110 240.9h.2M110 240.8h1.7M110 240.7h1.7"/>
<path d="M110.1 240.6h1.6M110.4 242.6h.9M110.6 242.5h.5M110.6 242.4h.5M110.6 240.9h.5M110.7 242.3h.4M110.7 241l-.1-.1h-.3l-.4 .2 .2-.5h1.6l.1 .5-.4-.2h-.3v.1M110.7 242.3l-.3 .3M110.7 242.2h.4M110.7 242.1h.4M110.7 242h.4M110.7 241.9h.4"/>
<path d="M110.7 241.8h.4M110.7 241.7h.4M110.7 241.6h.4M110.7 241.5h.4M110.7 241.4h.4M110.7 241.3h.4M110.7 241.2h.4M110.7 241.1h.4M110.7 241h.4M110.7 241v1.3M111.1 242.3l.2 .3M111.1 241v1.3"/>
<path d="M111.3 242.6h-.9M111.5 240.9h.3M111.7 241h.1M111.7 241.1h.1M111.9 242.6h.8M111.9 240.6h1.3M112 240.7h1.5M112 242.5h.6M112.1 240.8h1.5M112.1 242.4h.4M112.1 240.9h.4M112.1 242.3l-.2 .3"/>
<path d="M112.1 242.3h.4M112.1 242.2h.4M112.1 242.1h.4M112.1 242h.4M112.1 241.9h.4M112.1 241.8h1.2M112.1 241.7h1.3M112.1 241.6h1.5M112.1 241.5h.4M112.1 241.4h.4M112.1 241.3h.4M112.1 241.2h.4"/>
<path d="M112.1 241.1h.4M112.1 241h.4M112.1 240.9v1.4M112.1 240.9l-.2-.3h1.2l.5 .2 .1 .6-.5 .3 .9 .9h-.6l-.7-.8h-.3v.5M112.5 242.3l.2 .3M112.7 240.9l-.2 .1v.6M112.7 242.6h-.8M112.9 240.9h.3l.1 .3-.1 .3-.3 .1M112.9 241.9h.5M113 242h.5M113.1 242h.5M113.1 242.1h.6"/>
<path d="M113.1 240.9h.6M113.2 241.5h.5M113.2 242.2h.5M113.2 242.3h.6M113.2 241h.5M113.2 241.4h.5M113.3 241.3h.4M113.3 241.1h.4M113.3 241.2h.4M113.3 242.4h.5M113.4 242.5h.6M113.5 242.6h.6"/>
<path d="M113.9 240.6h.9M114 240.7h.6M114.1 240.8h.5M114.1 240.9h.5M114.1 240.9l-.2-.3h.9l-.2 .3M114.1 240.9v1.2l.3 .5 .6 .1 .5-.1 .3-.2 .1-.4M114.1 242h.5M114.1 241.9h.5M114.1 241.8h.5M114.1 241.7h.5M114.1 241.6h.5M114.1 241.5h.5"/>
<path d="M114.1 241.4h.5M114.1 241.3h.5M114.1 241.2h.5M114.1 241.1h.5M114.1 241h.5M114.1 242.1h.5M114.2 242.2h.4M114.2 242.3h.5M114.3 242.4h.6M114.4 242.5h1.3M114.6 242l.1 .3 .4 .1 .4-.1 .1-.3M114.6 241v1"/>
<path d="M114.6 242.6h.9M115.3 242.4h.5M115.4 240.6h.7M115.5 242.3h.3M115.5 240.7h.5M115.6 242.2h.2M115.6 242.1h.3M115.6 240.8h.3M115.6 242h.3M115.6 240.9h.3M115.6 240.9l-.2-.3h.7l-.2 .3M115.6 241.9h.3"/>
<path d="M115.6 241.8h.3M115.6 241.7h.3M115.6 241.6h.3M115.6 241.5h.3M115.6 241.4h.3M115.6 241.3h.3M115.6 241.2h.3M115.6 241.1h.3M115.6 241h.3M115.6 240.9v1.1M115.9 241v1M116.2 242.6h.6"/>
<path d="M116.2 240.6h.7M116.3 240.7h.7M116.3 242.5h.4M116.4 240.8h.6M116.4 242.4h.3M116.4 240.9h.7M116.4 242.3h.2M116.4 240.9l-.2-.3h.7l.6 1.3 .6-1.3h.7l-.2 .3M116.4 242.3l-.2 .3M116.4 242.2h.2M116.4 242.1h.2M116.4 242h.2"/>
<path d="M116.4 241.9h.2M116.4 241.8h.2M116.4 241.7h.2M116.4 241.6h.2M116.4 241.5h.2M116.4 241.4h.2M116.4 241.3h.2M116.4 241.2h.2M116.4 241.1h.7M116.4 241h.7M116.4 240.9v1.4M116.6 242.3l.2 .3"/>
<path d="M116.7 241.2h.5M116.8 241.3h.4M116.8 241.4h.5M116.8 242.6h-.6M116.8 241.5h.5M116.9 241.6h.4M116.9 241.7h.5M117 241.8h.4M117 241.9h.5M117 242h.7M117.1 242h.6M117.1 242.1h.6"/>
<path d="M117.2 242.2h.4M117.2 242.3h.4M117.3 242.4h.2M117.3 242.5h.2M117.3 242.6h.2M117.5 241.9h.3M117.6 241.8h.2M117.6 241.7h.3M117.7 241.6h.2M117.7 241.5h.3M117.7 241.4h.3M117.8 241.3h.2"/>
<path d="M117.8 241.2h.3M117.9 241.1h.7M117.9 241h.7M117.9 240.9h.7M118 242.6h.8M118 240.8h.6M118 240.7h.7M118.1 240.6h.7M118.1 242.5h.5M118.1 242.4h.5M118.1 242.3h.5M118.1 242.3l-.1 .3"/>
<path d="M118.1 242.3v-1.3l-.7 1.7-.8-1.7v1.3M118.1 242.2h.5M118.1 242.1h.5M118.1 242h.5M118.1 241.9h.5M118.1 241.8h.5M118.1 241.7h.5M118.1 241.6h.5M118.1 241.5h.5M118.1 241.4h.5M118.1 241.3h.5M118.1 241.2h.5"/>
<path d="M118.6 242.3l.2 .3M118.6 241v1.3M118.8 242.6h-.8M118.9 242.6h1.7M118.9 240.6h1.6M119.1 240.7h1.5M119.1 242.5h1.6M119.1 240.8h1.5M119.1 242.4h1.6M119.1 240.9h.5M119.1 240.9l-.2-.3h1.6l.1 .5M119.1 242.3h.5"/>
<path d="M119.1 242.2h.5M119.1 242.1h.5M119.1 242h.5M119.1 241.9h.5M119.1 241.8h.5M119.1 241.7h1.3M119.1 241.6h1.3M119.1 241.5h1.3M119.1 241.4h.5M119.1 241.3h.5M119.1 241.2h.5M119.1 241.1h.5"/>
<path d="M119.1 241h.5M119.1 240.9v1.4M119.1 242.3l-.2 .3M119.6 241.7v.7h.8l.3-.3M119.6 241v.5M119.7 240.9l-.1 .1M120.1 241.5l.3-.2v.6l-.3-.2M120.1 240.9l.5 .2M120.3 241.8h.1M120.3 241.4h.1M120.4 241.9h.1M120.4 240.9h.2"/>
<path d="M120.5 242.3h.2M120.5 241h.2M120.6 241.1h.1M120.7 242.2h.1M120.7 242.1h.1M120.7 242.1l-.1 .5h-1.7M120.8 242.6h.7M120.8 240.6h.7M120.9 240.7h.6M121 242.5h.4M121 240.8h.6M121 242.4h.3"/>
<path d="M121 240.9h.7M121 242.3h.3M121 240.9l-.2-.3h.6l1.1 1.2M121 242.3l-.2 .3M121 242.2h.3M121 242.1h.3M121 242h.3M121 241.9h.3M121 241.8h.3M121 241.7h.3M121 241.6h.3M121 241.5h.3"/>
<path d="M121 241.4h.3M121 241.3h.3M121 241.2h.3M121 241.1h.9M121 241h.8M121 240.9v1.4M121.3 242.3l.2 .3M121.3 241.1h.1M121.3 241.1v1.2M121.4 241.2h.6M121.5 241.3h.5M121.5 242.6h-.7"/>
<path d="M121.5 241.4h.6M121.6 241.5h.6M121.7 241.6h.6M121.8 241.7h.6M121.9 241.8h.8M122 241.9h.7M122 242h.7M122.1 242h.6M122.2 242.1h.5M122.3 242.2h.4M122.3 240.6h.6M122.4 242.3h.3"/>
<path d="M122.4 240.7h.4M122.5 242.4h.2M122.5 240.8h.3M122.5 241.8h.1M122.5 240.9h.2M122.5 240.9l-.2-.3h.6l-.2 .3M122.5 241.7h.2M122.5 241.6h.2M122.5 241.5h.2M122.5 241.4h.2M122.5 241.3h.2M122.5 241.2h.2"/>
<path d="M122.5 241.1h.2M122.5 241h.2M122.5 240.9v.9M122.5 242.5h.2M122.6 242.6h.1M122.7 240.9v1.8l-1.4-1.6M123 241.1h.1M123 241h.1M123 240.9h.2M123 240.8h1.8M123.1 240.7h1.7M123.1 240.6h1.6"/>
<path d="M123.5 242.6h.8M123.6 242.5h.6M123.7 242.4h.4M123.7 240.9h.4M123.7 241l-.3-.1-.5 .2 .2-.5h1.6l.2 .5-.4-.2h-.3l-.1 .1M123.7 242.3l-.2 .3M123.7 242.3h.4M123.7 242.2h.4M123.7 242.1h.4M123.7 242h.4M123.7 241.9h.4M123.7 241.8h.4"/>
<path d="M123.7 241.7h.4M123.7 241.6h.4M123.7 241.5h.4M123.7 241.4h.4M123.7 241.3h.4M123.7 241.2h.4M123.7 241.1h.4M123.7 241h.4M123.7 241v1.3M124.1 242.3l.2 .3M124.1 241v1.3M124.3 242.6h-.8"/>
<path d="M124.6 240.9h.2M124.7 241h.2M124.8 241.1h.1M124.9 242l.7 .4 .6-.1-.1-.4-.8-.2-.3-.3 .1-.6 .6-.2h.6l.2 .5-.8-.3-.3 .2v.2l1 .4 .2 .4M124.9 242h.1M125 242.1h.1M125 242.2h.2M125 241.2h.4M125 241.1h.4M125 241.3h.5M125 242.3h.4M125 241h.4"/>
<path d="M125 241.4h.9M125 242.4h.7M125.1 240.9h.4M125.1 242.5h1.3M125.1 241.5h1.1M125.1 242.6h.1M125.1 240.8h1.3M125.2 241.6h1.2M125.2 240.7h1.2M125.3 241.7h1.2M125.4 242.6h.8M125.4 240.6h.6"/>
<path d="M125.6 241.8h1M125.9 242.4h.6M126 241.9h.6M126.1 240.9h.3M126.1 242.3h.5M126.2 242h.4M126.2 242.2h.4M126.2 242.1h.4M126.2 240.6h.1M126.3 241h.2M126.4 241.1h.1M126.6 242l-.2 .5-.6 .2-.5-.1h-.2l-.2-.6"/>
<circle cx="113.2" cy="112.5" r=".83"/>
<circle cx="120.8" cy="112.5" r="1.25"/>
</g>
<g fill="#000">
<path d="M57.3 53.7l1.7-.3v.6zM103.9 53.4l1.7 .3-1.7 .3zM154 56.9l1.7 .3-1.7 .3zM156.4 54.5l1.5-.8 .2 .6zM154.8 51.7l1.6-1v1.9zM156.4 57.2l1.7-.3v.6zM49.6 66l.3 1.6h-.7zM49.6 64.3l.9 1.7h-1.9zM73.9 67.4l.2-.2 .3 .1 .2 .2-.2 .3-.3 .1-.2-.2zM111 66h.7l-.3 1.6zM111.4 72.6l.3 1.6h-.7zM115.6 67.6l.3 1.7h-.7z"/>
<path d="M49.2 102h.7l-.3 1.7zM63.2 109.2l1.7-1v2zM64.9 109.2l1.7-.3v.6zM96.4 108.9l1.7 .3-1.7 .3zM111.6 99.4h.7l-.4 1.6zM111.9 102.9l.4 1.7h-.7zM115.2 100.3h.7l-.3 1.7zM68 131.3l1.4 1-.5 .4zM110.4 129.9l.2 1.7h-.6zM110.3 127.1h.6l-.4 1.7zM50.4 152.8l.3 1.7h-.7zM174.1 153.4l.3 1.7h-.6z"/>
<path d="M50 174.6h.7l-.3 1.7zM87.2 170.3l.2-.2 .3 .1 .1 .3-.1 .2-.3 .1-.2-.2zM123.8 170.7h.7l-.5 1.6zM124.1 173.2l.5 1.6-.6 .1zM128.6 166.5h.7l-.4 1.7zM128.9 172.3l.4 1.7h-.7zM133.9 177.8l1.6 .4-1.6 .3zM146 178.2l1.7-.4v.7zM168.9 168.5h.7l-.3 1.7zM169.3 172.3l.3 1.7h-.7zM173.8 170.7h.6l-.3 1.6zM73.5 188l1.7-.3v.7z"/>
<path d="M87.7 187.7l1.7 .3-1.7 .4z"/>
</g>
<path d="M33.3 45.1h149.2v156.8h-149.2z" fill="none" stroke="#000" stroke-width=".36"/>
<path d="M33.3 38.2h149M33.3 233h149" fill="none" stroke="#000" stroke-width=".53"/>
<g fill="none" stroke="#000" stroke-width=".2" stroke-dasharray=".7 .7" stroke-linecap="butt">
<path d="M64.9 66.7l.7-.7M64.9 67.2l1.2-1.2M64.9 67.7l1.7-1.7M64.9 68.2l2.2-2.2M64.9 68.7l2.7-2.7M64.9 69.2l3.2-3.2M64.9 69.6l3.7-3.6M64.9 70.1l4.2-4.1M64.9 70.6l4.7-4.6M64.9 71.1l5.1-5.1M64.9 71.6l5.6-5.6M64.9 72.1l6.1-6.1"/>
<path d="M64.9 72.6l6.6-6.6M64.9 73.1l7.1-7.1M64.9 73.6l7.6-7.6M64.9 74.1l8.1-8.1M64.9 74.6l8.6-8.6M64.9 75l9.1-9M64.9 75.5l9.6-9.5M64.9 76l10.1-10M64.9 76.5l10.5-10.5M64.9 77l11-11M65.1 77.3l11.1-11.1M65.6 77.3l10.6-10.6"/>
<path d="M66.1 77.3l10.1-10.1M66.6 77.3l9.6-9.6M67.1 77.3l9.1-9.2M67.6 77.3l8.6-8.7M68.1 77.3l8.1-8.2M68.5 77.3l7.7-7.7M69 77.3l7.2-7.2M69.5 77.3l6.7-6.7M70 77.3l6.2-6.2M70.5 77.3l5.7-5.7M71 77.3l5.2-5.2M71.5 77.3l4.7-4.7"/>
<path d="M72 77.3l4.2-4.2M72.5 77.3l3.7-3.8M73 77.3l3.2-3.3M73.5 77.3l2.7-2.8M73.9 77.3l2.3-2.3M74.4 77.3l1.8-1.8M74.9 77.3l1.3-1.3M75.4 77.3l.8-.8M75.9 77.3l.3-.3M76.2 66v11.3M76.2 77.3h-11.3M134.1 168.2h31.8"/>
</g>
<g fill="none" stroke="#007fff" stroke-width=".2">
<path d="M64.9 66.7h-7.6v1.9h7.6M64.9 71.6h-7.6v1.9h7.6M64.9 76.5h-7.6v1.9h7.6M98.1 76.5h7.5v1.9h-7.5M98.1 71.6h7.5v1.9h-7.5M98.1 66.7h7.5v1.9h-7.5M151.3 66.7h.1M151.3 66v.7M151.3 66h1.1l2.5 .5 .4 .2M151.3 66l-2.8 .5a.75 .75 0 0 0-.6 .8v35a.75 .75 0 0 0 .6 .8l2.8 .6M151.3 76.5h5.1v1.9h-5.1M151.3 71.6h5.1v1.9h-5.1"/>
<path d="M151.3 66.7h5.1v1.9h-5.1M151.3 66.7v36.2M152.4 66.7h.1M152.4 68.6v3M152.4 73.5v3M152.4 78.4v3M152.4 66v.7M155.3 66.7v1.9M155.3 71.6v1.9M155.3 76.5v1.9M155.5 68.6v3M155.5 73.5v3"/>
<path d="M155.5 78.4v3M64.9 81.4h-7.6v1.9h7.6M64.9 86.3h-7.6v1.9h7.6M64.9 91.2h-7.6v1.9h7.6M64.9 96.1h-7.6v1.9h7.6M98.1 96.1h7.5v1.9h-7.5M98.1 91.2h7.5v1.9h-7.5M98.1 86.3h7.5v1.9h-7.5M98.1 81.4h7.5v1.9h-7.5M151.3 96.1h5.1v1.9h-5.1M151.3 91.2h5.1v1.9h-5.1M151.3 86.3h5.1v1.9h-5.1"/>
<path d="M151.3 81.4h5.1v1.9h-5.1M152.4 83.3v3M152.4 88.2v3M152.4 93.1v3M152.4 98v3M155.3 81.4v1.9M155.3 86.3v1.9M155.3 91.2v1.9M155.3 96.1v1.9M155.5 83.3v3M155.5 88.2v3M155.5 93.1v3"/>
<path d="M155.5 98v3M64.9 102.9v-36.2l.2-.5 .5-.2h31.7l.5 .2 .3 .5v36.2M64.9 102.9a.75 .75 0 0 0 .7 .8h31.7a.75 .75 0 0 0 .8-.8M64.9 101h-7.6v1.9h7.6M98.1 101h7.5v1.9h-7.5M151.3 102.9v.8M151.3 102.9h.1M151.3 103.7h1.1M151.3 101h5.1v1.9h-5.1M152.4 102.9h.1M152.4 102.9v.8M155.3 101v1.9l-.1 .1-2.8 .7"/>
<path d="M64.9 125.6l.5 2.4a.75 .75 0 0 0 .7 .6h30.7a.75 .75 0 0 0 .8-.6l.5-2.4M64.9 124.5l.6-2.8a.75 .75 0 0 1 .7-.6h30.5a.75 .75 0 0 1 .8 .6l.6 2.8v1.1M64.9 124.5a3.3 3.3 0 0 0-3.4 .9l-.4 1a1.71 1.71 0 0 1-.8 1.8l-3 .3 .1 1.1 2.6-.2a2.26 2.26 0 0 0 2.1-1.9 1.67 1.67 0 0 1 .9-1.8l1.9-.1M64.9 124.5h32.4M64.9 124.5v1.1M97.3 125.6h.1M97.3 125.6h-32.4M97.3 124.5h.8a4.4 4.4 0 0 1 3 .5 2.99 2.99 0 0 1 .9 2.3 1.13 1.13 0 0 0 1 1l2.6 .2-.1 1.1-2.6-.2a2.26 2.26 0 0 1-2-1.9l-.2-1a1.13 1.13 0 0 0-1.1-.9h-1.5M97.3 124.5h.1M97.3 125.6h.8M57.4 146.5v1.8M57.4 151.4v1.8"/>
<path d="M57.4 156.3v1.8M64.9 146.4a.75 .75 0 0 1 .7-.7h31.7l.5 .2 .3 .5M64.9 146.4v36.3a.75 .75 0 0 0 .7 .7h31.7l.5-.2 .3-.5v-36.3M64.9 146.5h-7.6v1.8h7.6M64.9 151.4h-7.6v1.8h7.6M64.9 156.3h-7.6v1.8h7.6M73.5 152.8h15.9v23.5h-15.9zM98.1 146.5h7.5v1.8h-7.5M98.1 151.4h7.5v1.8h-7.5M98.1 156.3h7.5v1.8h-7.5M105.5 146.5v1.8M105.5 151.4v1.8"/>
<path d="M105.5 156.3v1.8M57.4 161.2v1.8M57.4 166.1v1.8M57.4 171v1.8M57.4 175.9v1.8M64.9 161.2h-7.6v1.8h7.6M64.9 166.1h-7.6v1.8h7.6M64.9 171h-7.6v1.8h7.6M64.9 175.9h-7.6v1.8h7.6M98.1 161.2h7.5v1.8h-7.5M98.1 166.1h7.5v1.8h-7.5M98.1 171h7.5v1.8h-7.5"/>
<path d="M98.1 175.9h7.5v1.8h-7.5M105.5 161.2v1.8M105.5 166.1v1.8M105.5 171v1.8M105.5 175.9v1.8M152.3 160.9h-3.4a5 5 0 0 0-5 4.3 4.5 4.5 0 0 1-1.1 3.6l-.9 .5-.6 .1-5.8 .4 .2 2.5 5.8-.4a5 5 0 0 0 4.6-4.2 4.4 4.4 0 0 1 1.2-3.6l1-.6h.6h3.4M152.3 160.9l1.3-6.2a1.68 1.68 0 0 1 1.7-1.3h9.1l.1 .7-1.3 2 .7 3.2-.4 .9-.6 .9-.3 1 1.2 2.6-.4 .9-1.1 1.8 .1 .9 .8 1.9h-8.1a1.68 1.68 0 0 1-1.7-1.4l-1.1-5.3M152.3 160.9v2.6M152.3 160.9h10.7M163.2 163.5h-10.9M57.4 180.8v1.8M64.9 180.8h-7.6v1.8h7.6"/>
<path d="M98.1 180.8h7.5v1.8h-7.5M105.5 180.8v1.8"/>
<circle cx="70.9" cy="72" r="3"/>
</g>
<g fill="none" stroke="#000" stroke-width=".2" stroke-dasharray="2.8 .7 .7 .7 .7 .7" stroke-linecap="butt">
<path d="M155.7 104.3v-39.8"/>
<circle cx="62.5" cy="125.7" r="7.8"/>
</g>
<path d="M171.5 11.6l-.2 .6 .5-.2h.6v.1v2.2l-.2 .4h1l-.2-.4v-2.2v-.1h.5l.6 .2-.2-.6zM173.6 12.4l.2 .3v1.6l-.2 .4h1.9l.1-.6a1.08 1.08 0 0 1-1.3 .2v-.7h.6l.4 .2v-.7l-.4 .2h-.6v-.5l.2-.2a1 1 0 0 1 1 .3l-.1-.5zM175.7 12.4l.9 1.1-1 1.2h.9l-.2-.2 .5-.8 .4 .8-.2 .2h1.6l-.2-.2 .2-.5h.9l.1 .5-.1 .2h.9l-.2-.4-.8-1.9h-.5l-.9 2.1-.9-1.1 .9-1h-.8l.2 .2-.4 .6-.4-.6 .2-.2zM179 12.8l.4 1h-.7zM180.7 12.5a.65 .65 0 0 0-.2 .7 .65 .65 0 0 0 .6 .5l.6 .1 .1 .3a.79 .79 0 0 1-.7 .4 .79 .79 0 0 1-.7-.5l.1 .7 .2-.1a.93 .93 0 0 0 1.1 0 .93 .93 0 0 0 .4-.9 1.46 1.46 0 0 0-1.2-.6l-.1-.3a1.09 1.09 0 0 1 1.2 .2l-.2-.6-.1 .1-.5-.2zM172.2 15.2l.2 .4v2.2l-.2 .4h1l-.2-.4v-2.2l.2-.4zM173.4 15.9l.2 .4v1.5l-.2 .4h.8l-.3-.4 .1-1.3 1.6 1.8v-2l.2-.4h-.7l.1 .2 .1 1.1-1.2-1.3zM176.2 16a.65 .65 0 0 0-.2 .8 .65 .65 0 0 0 .6 .4l.6 .2 .1 .2a.79 .79 0 0 1-.7 .4 .79 .79 0 0 1-.7-.5l.1 .7 .2-.1a.93 .93 0 0 0 1.1 .1 .93 .93 0 0 0 .4-1 1.46 1.46 0 0 0-1.2-.5l-.1-.4a1.09 1.09 0 0 1 1.2 .2l-.1-.6-.2 .1-.5-.1zM177.9 15.9l-.1 .6a.63 .63 0 0 1 .8-.3v1.6l-.3 .4h1l-.2-.4v-1.6a.66 .66 0 0 1 .8 .3l-.1-.6zM180 15.9l.2 .4v1.5l-.2 .4h1l-.2-.2-.1-.7h.5l.1 .2a.79 .79 0 0 0 1.2 .6l-1-.9a.61 .61 0 0 0 .6-.6 .61 .61 0 0 0-.5-.7zM180.8 16.2h.1a.47 .47 0 0 1 .5 .1 .47 .47 0 0 1 .1 .5l-.1 .1-.7 .1zM182.3 15.9l.2 .2a2.27 2.27 0 0 0 .4 2 1.04 1.04 0 0 0 1.7-.7v-1.3l.2-.2h-.8l.2 .4v1.1a.6 .6 0 0 1-.6 .6 .6 .6 0 0 1-.6-.6v-1.1l.3-.4zM184.9 15.9l.2 .4v1.5l-.2 .4h.8l-.3-.4v-1.4l.9 1.9 .9-1.9v1.4l-.3 .4h1l-.2-.4v-1.5l.2-.4h-.8l-.7 1.5-.6-1.5zM188.1 15.9l.2 .4v1.5l-.2 .4h1.9l.1-.6a1.09 1.09 0 0 1-1.3 .2v-.7h.6l.4 .2v-.6l-.4 .2h-.6v-.6l.2-.1a1.01 1.01 0 0 1 1 .3l-.1-.6zM190.2 15.9l.3 .4v1.5l-.3 .4h.8l-.2-.4v-1.3l1.6 1.8v-2l.2-.4h-.7l.2 .2v1.1l-1.2-1.3zM192.8 15.9l-.1 .6a.63 .63 0 0 1 .8-.3v1.6l-.3 .4h1l-.2-.4v-1.6a.66 .66 0 0 1 .8 .3l-.1-.6zM195.2 16a.65 .65 0 0 0-.2 .8 .65 .65 0 0 0 .6 .4l.6 .2 .2 .2a.79 .79 0 0 1-.7 .4 .79 .79 0 0 1-.7-.5l.1 .7 .2-.1a.93 .93 0 0 0 1 .1 .93 .93 0 0 0 .5-1 1.46 1.46 0 0 0-1.3-.5v-.4a1.09 1.09 0 0 1 1.2 .2l-.2-.6-.2 .1-.5-.1z" fill="#231f20"/>
<path d="M164.9 10.3v2.7h-2l.1 .4 .8 1a.95 .95 0 0 0 1 .9 .59 .59 0 0 1 .5-.4 .59 .59 0 0 1 .5 .3l.4 .8a1.59 1.59 0 0 0 2.1 1.4 1.61 1.61 0 0 1 1-2.3l1-.3-.1-1.5a1.59 1.59 0 0 1-.3-1.7h-1.5l-.2 .9h.6l-.2 .9h-.5l-.2 .9v.3l.4 .1-.1 .9h-.7a.73 .73 0 0 1-1-.7l.3-1.5h-.5l.1-.9h.5l.2-.9h-.5v-1.3zM167.4 11.6l-.6 3.1h.7l.6-3.1zM167.6 10.7l-.1 .6h.7l.1-.6z" fill="#ed1c24"/>
<path d="M19 22.9h177.8M19 262.3h180" fill="none" stroke="#000" stroke-width=".53"/>
<use href="#words"/>
</svg>
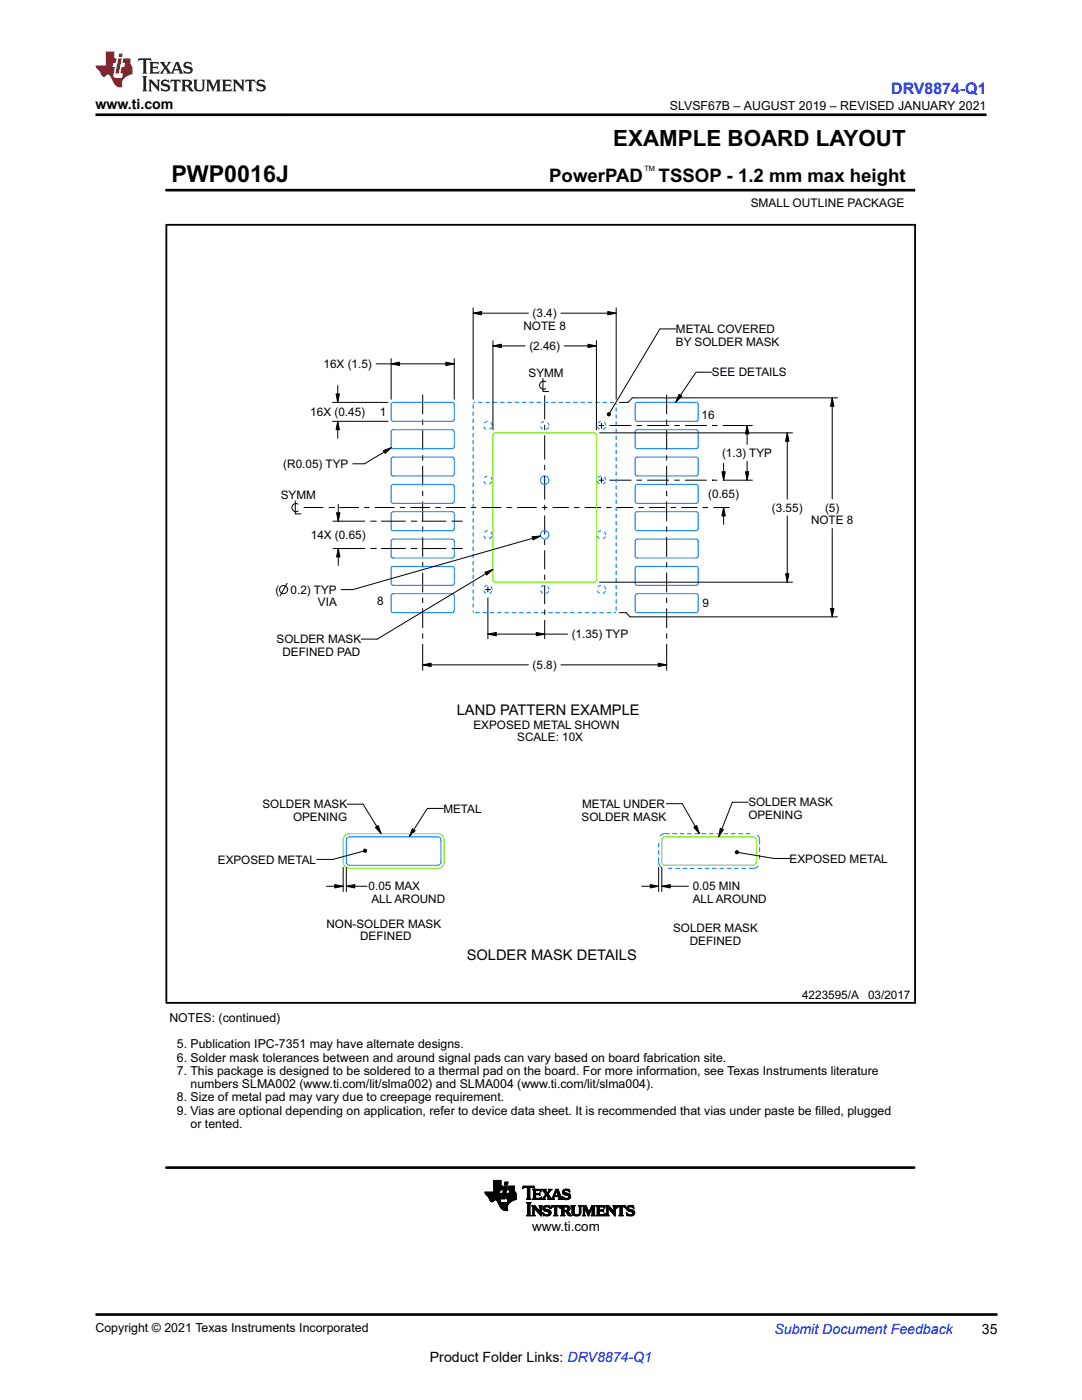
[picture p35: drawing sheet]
<svg xmlns="http://www.w3.org/2000/svg" width="216mm" height="279mm" viewBox="0 0 216 279" stroke-linecap="round" stroke-linejoin="round" font-family="sans-serif">
<defs><g id="words">
<text font-size="4.6" x="34.2" y="36.3">PWP0016J</text>
<text font-size="4.5" x="122.4" y="29.1">EXAMPLE BOARD LAYOUT</text>
<g font-size="3.7">
<text x="109.6" y="36.3">PowerPAD</text>
<text x="131.4" y="36.3">TSSOP - 1.2 mm max height</text>
</g>
<text font-size="3.2" fill="#00f" x="177.8" y="18.7">DRV8874-Q1</text>
<g font-size="2.9">
<text x="91.1" y="142.8">LAND PATTERN EXAMPLE</text>
<text x="93.1" y="191.6">SOLDER MASK DETAILS</text>
</g>
<g font-size="2.8">
<text x="19" y="21.8">www.ti.com</text>
<text x="195.9" y="266.1">35</text>
<text x="85.8" y="271.7">Product Folder Links: DRV8874-Q1</text>
</g>
<text font-size="2.8" fill="#00f" x="154.5" y="266.2">Submit Document Feedback</text>
<text font-size="2.7" x="106.2" y="245.6">www.ti.com</text>
<g font-size="2.5">
<text x="133.7" y="21.9">SLVSF67B – AUGUST 2019 – REVISED JANUARY 2021</text>
<text x="33.8" y="204">NOTES: (continued)</text>
<text x="35.3" y="209.3">5. Publication IPC-7351 may have alternate designs.</text>
<text x="35.3" y="211.9">6. Solder mask tolerances between and around signal pads can vary based on board fabrication site.</text>
<text x="35.3" y="214.5">7. This package is designed to be soldered to a thermal pad on the board. For more information, see Texas Instruments literature</text>
<text x="35.3" y="219.8">8. Size of metal pad may vary due to creepage requirement.</text>
<text x="38" y="217.2">numbers SLMA002 (www.ti.com/lit/slma002) and SLMA004 (www.ti.com/lit/slma004).</text>
<text x="35.3" y="222.5">9. Vias are optional depending on application, refer to device data sheet. It is recommended that vias under paste be f</text>
<text x="38" y="225.1">or tented.</text>
<text x="162.7" y="222.5">illed, plugged</text>
<text x="19" y="265.9">Copyright © 2021 Texas Instruments Incorporated</text>
</g>
<text font-size="2.4" x="149.8" y="41.3">SMALL OUTLINE PACKAGE</text>
<g font-size="2.3">
<text x="104.5" y="65.9">NOTE 8</text>
<text x="106.3" y="63.3">(3.4)</text>
<text x="105.6" y="69.9">(2.46)</text>
<text x="134.9" y="66.5">METAL COVERED</text>
<text x="134.9" y="69">BY SOLDER MASK</text>
<text x="64.6" y="73.5">16X (1.5)</text>
<text x="105.5" y="75.2">SYMM</text>
<text x="142.1" y="75.1">SEE DETAILS</text>
<text x="61.9" y="83">16X (0.45)</text>
<text x="75.8" y="83">1</text>
<text x="140" y="83.5">16</text>
<text x="56.5" y="93.4">(R0.05) TYP</text>
<text x="144.1" y="91.2">(1.3) TYP</text>
<text x="56" y="99.6">SYMM</text>
<text x="141.3" y="99.4">(0.65)</text>
<text x="62" y="107.6">14X (0.65)</text>
<text x="154" y="102.1">(3.55)</text>
<text x="161.8" y="104.6">NOTE 8</text>
<text x="164.6" y="102.1">(5)</text>
<text x="55" y="118.5">(</text>
<text x="58" y="118.5">0.2) TYP</text>
<text x="63.4" y="121">VIA</text>
<text x="75.3" y="120.7">8</text>
<text x="140.2" y="121.2">9</text>
<text x="55.2" y="128.4">SOLDER MASK</text>
<text x="56.3" y="130.9">DEFINED PAD</text>
<text x="114.1" y="127.4">(1.35) TYP</text>
<text x="106.3" y="133.5">(5.8)</text>
<text x="94.5" y="145.4">EXPOSED METAL SHOWN</text>
<text x="103.2" y="147.9">SCALE: 10X</text>
<text x="52.4" y="161.3">SOLDER MASK</text>
<text x="116.2" y="161.2">METAL UNDER</text>
<text x="149.3" y="160.9">SOLDER MASK</text>
<text x="58.5" y="163.8">OPENING</text>
<text x="88.5" y="162.2">METAL</text>
<text x="116" y="163.8">SOLDER MASK</text>
<text x="149.3" y="163.5">OPENING</text>
<text x="43.5" y="172.4">EXPOSED METAL</text>
<text x="157.5" y="172.2">EXPOSED METAL</text>
<text x="73.6" y="177.7">0.05 MAX</text>
<text x="138.2" y="177.7">0.05 MIN</text>
<text x="65.2" y="185.2">NON-SOLDER MASK</text>
<text x="74.1" y="180.2">ALL AROUND</text>
<text x="138.2" y="180.2">ALL AROUND</text>
<text x="71.9" y="187.7">DEFINED</text>
<text x="134.3" y="186">SOLDER MASK</text>
<text x="137.6" y="188.5">DEFINED</text>
<text x="160" y="199.3">4223595/A</text>
<text x="173.2" y="199.3">03/2017</text>
</g>
<text font-size="1.5" x="128.6" y="34">TM</text>
</g></defs>
<g fill="none" stroke="#000" stroke-width=".2">
<path d="M33.2 38h149.2M182.4 37.7v.5M67.1 78.6h.6l-.3 1.7zM67.4 76.9v3.4M75 72.6h15.6M78 72.6l1.7-.3v.7zM78 71.6v8.1M84.3 78.7v4M89 72.3l1.6 .3-1.6 .4zM90.6 71.6v8.1M94.4 62.5l1.7-.3v.6zM94.4 61.5v18.2"/>
<path d="M94.4 62.5h11M98.4 69l1.6-.3v.7zM98.4 68v17.8M98.4 69h6.4M108.3 75.6v2.5h1.2M108.7 78.9v4.8M108.9 76.2a.82 .82 0 0 0-1.3 .7 .82 .82 0 0 0 1.3 .7M111.9 62.5h11.1M112.6 69h6.4M117.3 68.7l1.7 .3-1.7 .4zM119 68v17.8M121.3 62.2l1.7 .3-1.7 .3z"/>
<path d="M123 61.5v18.2M133 78.7v4M134.9 65.6h-3.2l-10 16.8M135.5 78.7l.6 .4-1.3 1.2zM142.1 74.3h-3.2l-4.1 6M166.1 79.4l.3 1.7h-.7zM166.1 79.4v20.2M167.1 79.4h-40.9l-.9 .9h-1.7M58.9 100v2.6h1.1M66.3 84.1h11.1M66.3 80.3h11.1M67.4 84.1l.3 1.7h-.6z"/>
<path d="M67.4 84.1v3.3M76.5 89.9l1.6-.6-1.3 1.2zM78.1 89.3l-5.4 3.3h-2.3M84.3 83.7v1.1M84.3 85.9v3.9M84.3 90.8v1.1M84.3 93v3.9M84.3 98v1M108.7 84.8v1M108.7 86.9v4.8M108.7 92.8v1M108.7 94.9v4.8"/>
<path d="M119.4 84.9h1.1M119.5 95.8h1M119.6 86.4h38.5M120 84.4v1.1M120 95.2v1.2M121.2 82.5l.2-.1h.3l.1 .3-.1 .2-.3 .1-.2-.2zM121.6 95.8h4.4M121.6 84.9h4.4M127 95.8h1.1M127 84.9h1.1M129.1 95.8h4.4M129.1 84.9h4.4"/>
<path d="M133 83.7v1.1M133 85.9v3.9M133 90.9v1M133 93v3.9M133 98v1M134.6 95.8h1M134.6 84.9h1M136.7 95.8h4.3M136.7 84.9h4.4M142.1 95.8h.1M142.1 95.8h1.1M142.1 84.9h.1"/>
<path d="M142.1 84.9h1.1M144.1 94.2h.6l-.3 1.6zM144.2 95.8h5.9M144.2 84.9h5.9M144.4 92.5v3.3M148.7 94.2h.7l-.3 1.6zM149.1 84.9l.3 1.7h-.7zM149.1 84.9v3.8M149.1 92.1v3.7M157.1 86.4l.3 1.7h-.6zM157.1 86.4v13.2M57.3 116.4l-1.4 2.5"/>
<path d="M59.5 100.6a.82 .82 0 0 0-1.3 .7 .82 .82 0 0 0 1.3 .7M60.6 101.3h3.9M65.6 101.3h1M66.4 109.5h6.4M66.4 104h6.4M66.6 101.3h.1M67.2 102.3h.6l-.3 1.7zM67.5 109.5l.3 1.6h-.6zM67.5 100.7v3.3M67.5 109.5v3.3M67.7 101.3h3.9M72.7 101.3h1"/>
<path d="M73.9 104h1.1M73.9 109.5h1.1M74.8 101.3h3.9M75 104h.1M75 109.5h.1M76 104h4.9M76 109.5h4.9M79.8 101.3h1M81.9 101.3h3.9M82 104h1.1M82 109.5h1.1M83.1 104h.1"/>
<path d="M83.1 109.5h.1M84.1 104h5M84.1 109.5h5M84.3 100.1v3.9M84.3 105.1v1M84.3 107.2v3.9M84.3 112.2v1M84.3 114.3v3.9M84.3 119.3v1M86.9 101.3h1M89 101.3h3.9M90.1 109.5h2.2"/>
<path d="M90.1 104h2.2M94 101.3h1M96.1 101.3h3.9M96.7 114.2l1.7-.6-1.3 1.2zM96.8 117.7h1.1M97.4 117.1v1.1M97.4 119.2v8.3M98.4 113.6l-23.1 13.9h-3.2M101.1 101.3h1M103.2 101.3h3.9M106.2 107.1l1.7-.1-1.5 .8zM107.9 107l-37.5 10.7h-2.3"/>
<path d="M108.2 101.3h1M108.7 100.8v1M108.7 102.9v3.8M108.7 107.7v1.1M108.7 109.8v3.8M108.7 114.7v1M108.7 116.8v3.8M110.3 101.3h3.2M114.6 101.3h1M116.7 101.3h3.2M119.6 116.2h38.5M121 101.3h1"/>
<path d="M123.1 101.3h3.2M127.4 101.3h1.1M129.5 101.3h3.3M133 100.1v3.9M133 105.1v1M133 107.2v3.9M133 112.2v1M133 114.3v3.9M133 119.3v1.1M133.8 101.3h1.1M135.9 101.3h3.3M140.2 101.3h.1"/>
<path d="M140.2 101.3h1.1M142.3 101.3h3.3M144.4 101.3l.3 1.7h-.6zM144.4 101.3v3.3M156.8 114.5h.6l-.3 1.7zM157.1 103v13.2M166.1 105.5v17.6M84.3 132.7l1.7-.3v.6zM84.3 121.4v3.9M84.3 126.4v1.1M84.3 128.5v5.3M84.3 132.7h21.1"/>
<path d="M97.4 126.6l1.6-.4v.7zM97.4 126.6h15.8M107 126.2l1.7 .4-1.7 .3zM108.7 121.6v1.1M108.7 123.7v3.8M111.9 132.7h21.1M123.6 122.3h1.3l.8 .8h41.4M131.3 132.4l1.7 .3-1.7 .3zM133 121.4v4M133 126.4v1.1M133 128.5v5.3M165.7 121.4h.7l-.3 1.7z"/>
<path d="M65.1 176.9h3.4M66.8 176.5l1.7 .4-1.7 .3zM68.5 173.1v4.8M69.1 176.9l1.7-.4v.7zM69.1 173.1v4.8M69.1 176.9h4.2M69.3 160.5h3.2l3.6 5.9M72.5 169.9l-6.1 1.6h-3.2M72.5 169.6l.3-.1h.2l.2 .3-.2 .2-.2 .1-.3-.2zM74.9 165.1l.6-.3 .6 1.6zM82.3 165.4l.5 .4-1.1 1.2zM88.5 161.3h-3.2l-3.6 5.7"/>
<path d="M128.1 176.9h3.3M129.7 176.5l1.7 .4-1.7 .3zM131.4 173.1v4.8M132.1 176.9l1.6-.4v.7zM132.1 176.9h5.3M132.1 173.1v4.8M132.9 160.4h3.2l3.5 6M138.4 165.1l.6-.3 .6 1.6zM143.7 165.3l.6 .3-.9 1.4zM146.7 169.9l.3-.1h.2l.2 .3-.2 .2-.2 .1-.3-.2zM147.4 170.1l7 1.2h3.1M149.3 160.1h-3.2l-2.7 6.9"/>
<path d="M96.8 238h2.9M96.8 238.1h2.9M96.8 238.2h2.8M96.9 238.2h3.2l-.2 1M96.9 238.3h3.1M96.9 238.4h3.1M97 238.4h3M97.1 238.5h2.9M97.1 238.6h2.9M97.2 238.6h2.8M97.3 238.7h2.7M97.4 238.8h2.5"/>
<path d="M97.5 238.9h2.4M97.6 239h2.3M97.6 239.1h2.3M97.6 239.2h2.3M97.7 239.3h2.1M97.7 239.4h2.1M97.7 239.5h1M97.8 239.5h.8M97.8 239.6h.7M97.9 239.7h.6M97.9 239.7h.5M98.1 239.8h.2"/>
<path d="M98.5 237.8h1.2M98.5 237.7h1.2M98.5 237.6h1.3M98.5 236.7h1.8l-.1 .8h-1.7M98.5 237.4h1.7M98.5 237.3h1.7M98.5 237.2h1.7M98.5 237.2h1.8M98.5 237.1h1.8M98.5 237h1.8M98.5 236.9h1.8M98.5 236.8h1.8"/>
<path d="M98.5 236.6h1.5M98.5 236.5h1.5M98.5 236.4h1.5M98.5 236.3h1.5M98.5 236.2h1.5M98.5 236.1h1.5M98.5 236h1.5M98.5 235.9h1.5M98.5 235.8h1.5M98.5 235.7h1.5M98.5 235.6h1.5M99 239.5h.8"/>
<path d="M99.1 239.5h.7M99.2 239.6h.6M99.2 239.7h.6M99.3 239.7h.5M99.3 239.8h.5M99.3 239.9h.6M99.4 239.9h.6M99.7 237.9h-2.9l.1 .4 .6 .6 .4 .8 .4 .1 .4-.3h.4l.8 1.5 .7 .5h.7l-.1-.8 .6-.8M99.8 237.5l-.2 .7M99.9 239.2l-.1 .6 .6 .2h.8l.2-.7M100 236.7v-1.1h-1.5v2.3M100.1 239.2h.6"/>
<path d="M100.1 239.1h.6M100.2 239h.5M100.2 238.9h.6M100.2 238.8h.6M100.2 238.7h.6M100.2 238.6h.6M100.3 238.6h.5M100.3 238.5h.5M100.3 238.4h.6M100.3 238.3h.6M100.3 238.2h.6M100.3 238.1h.6"/>
<path d="M100.4 238h.5M100.4 238h.6M100.4 237.9h.6M100.4 237.8h.6M100.4 237.7h.6M100.4 237.6h.6M100.5 237.5h.5M100.5 237.4h.6M100.5 237.3h.6M100.5 237.2h.6M100.5 237.1h.6M100.6 237h.5"/>
<path d="M100.6 237h.6M100.6 236.9h.6M100.6 236.8h.6M100.6 236.7h.6l-.5 2.6h-.6zM100.7 236.4h.6M100.7 236.3h.6M100.7 236.2h.6M100.7 236.1h.6M100.7 236h.6M100.8 236h.5M100.8 235.9h.6l-.2 .6h-.5zM101 239.1h2"/>
<path d="M101 239h2M101 239.2h2M101 238.9h2M101 238.9v.3l.4 .1M101 238.8h2M101.1 238.7h1.9M101.1 238.6h1.9M101.1 238.5h1.9M101.1 238.4h1.9M101.1 238.3h1.9M101.2 239.9h.6M101.3 239.9h.6"/>
<path d="M101.3 239.8h.7M101.3 239.7h.8M101.3 239.7h.9M101.3 239.6h1M101.3 237.4h1.4M101.3 239.5h1.2M101.3 239.5h1.3M101.3 237.3h1.4M101.3 239.4h1.5M101.4 237.2h1.3M101.4 239.3h1.6M101.4 237.1h1.3"/>
<path d="M101.4 237h1.3M101.4 236.9h1.3M101.4 236.8h1.3M101.6 238.2h1.4M101.6 238.1h1.3M101.6 238h1.2M101.7 237.9h1.1M101.7 237.8h1M101.7 237.7h1M101.7 237.6h1M101.7 237.5l-.1 .7M102.7 237.5h-1.4l.2-.8h1.2v1l.3 .5v1.2"/>
<path d="M103 239.4l-1.2 .5M103 238.2h-1.8l-.2 .7M104.2 237.2h.2M104.3 237.1h.2M104.3 237h2.3M104.3 236.9h2.3M104.4 236.8h2.2M105 239.3h.9M105.2 239.2h.6M105.2 237.1h.5M105.2 239.1h.5M105.2 237.1v-.1h-.4l-.6 .2 .2-.5h2.1l.2 .5-.5-.2h-.4l-.1 .1"/>
<path d="M105.2 239l-.2 .3M105.2 239h.5M105.2 238.9h.5M105.2 238.8h.5M105.2 238.7h.5M105.2 238.6h.5M105.2 238.5h.5M105.2 238.4h.5M105.2 238.3h.5M105.2 238.2h.5M105.2 238.1h.5M105.2 238h.5"/>
<path d="M105.2 237.9h.5M105.2 237.8h.5M105.2 237.7h.5M105.2 237.6h.5M105.2 237.5h.5M105.2 237.4h.5M105.2 237.3h.5M105.2 237.2h.5M105.2 237.1v1.9M105.7 239l.2 .3M105.7 237.1v1.9M105.9 239.3h-.9"/>
<path d="M106.2 239.3h1.7M106.3 237.4h1.6M106.4 239.2h1.6M106.4 237.5h1.5M106.4 239.1h.5M106.4 237.6h.5M106.4 237.7l-.2-.4h1.6l.2 .5M106.4 239l-.2 .3M106.4 238.2h1.1l.2-.2v.6l-.2-.2-1.1 .1M106.4 239h.5M106.4 238.9h.5M106.4 238.8h.5"/>
<path d="M106.4 238.7h.5M106.4 238.6h.5M106.4 238.4h1.3M106.4 238.3h1.3M106.4 238.1h.5M106.4 238h.5M106.4 237.9h.5M106.4 237.8h.5M106.4 237.7h.5M106.4 237.7v1.3M106.5 237.1h.2M106.6 237.2h.1"/>
<path d="M106.9 237.7l.1-.1h.5l.5 .2M106.9 238.4v.7h.8l.3-.2-.1 .5-1.7-.1M106.9 237.7v.5M107.5 238.2h.2M107.6 238.5h.1M107.6 239.1h.4M107.6 238.1h.1M107.6 238.6h.1M107.6 237.6h.3M107.8 237.7h.2M107.9 239h.1M107.9 237.8h.1"/>
<path d="M108 238.9h.1M108 239.3h.8M108.1 237.4h.8M108.3 239.2h.3M108.3 237.5h.6M108.3 239.1h.4M108.4 237.6h.5M108.4 239l-.4 .3M108.4 239h.3M108.4 237.7h.6M108.5 238.9h.3M108.5 237.8h.5"/>
<path d="M108.5 238.8h.3M108.6 237.9h.5M108.6 238.8h.3M108.6 238h.5M108.7 238.7h.3M108.7 238.1h.8M108.7 238.6h.8M108.8 238.2h.6M108.8 239.3h-.8M108.8 238.5h.7M108.8 238.3h.6M108.9 238.4h.5"/>
<path d="M108.9 237.7l.1-.4h-.9l.8 1.1-.5 .6M108.9 237.7l.3 .4 .4-.5-.2-.3h.7l-.7 1M109.1 238.7h.5M109.2 238.8h.5M109.3 239.3l.1-.2-.4-.6-.3 .7 .1 .1M109.3 239.3h1.4M109.3 238h.3M109.3 238.9h.5M109.3 237.9h.3M109.4 238.3l.7 .9 .2-.2M109.4 239h.5M109.4 237.8h.3"/>
<path d="M109.4 239.1h.5M109.4 239.2h.6M109.5 237.7h.3M109.5 237.4h.6M109.5 237.6h.3M109.6 237.5h.3M110.1 239.2h.4M110.2 239.1h.3M110.2 239h.3M110.3 239l.6-1.7h.5l.6 1.8 .3 .2M110.3 238.9h.3M110.3 238.8h.3"/>
<path d="M110.4 238.8h1.5M110.4 238.7h1.5M110.4 238.6h.3M110.5 238.5h.2M110.5 238.4h.3M110.5 239.1l.2 .2M110.5 239.1l.1-.3h.8l.1 .3M110.5 238.3h.3M110.6 238.2h.2M110.6 238.1h.3M110.7 239.3h-1.4M110.7 238h.2"/>
<path d="M110.7 237.9h.3M110.7 237.8h.3M110.8 237.7h.7M110.8 237.6h.7M110.8 237.5h.6M110.9 237.4h.5M111 237.7l.4 .9h-.7zM111.1 237.8h.4M111.1 237.9h.5M111.1 238h.5M111.2 238.1h.4M111.2 238.2h.5"/>
<path d="M111.2 238.3h.5M111.3 238.4h.5M111.3 238.5h.5M111.4 238.6h.4M111.4 239.3h.9M111.5 238.8h.4M111.5 238.9h.5M111.5 239h.5M111.5 239.1l-.1 .2M111.6 239.2h.5M111.6 239.1h.4M112.2 238.8h.1"/>
<path d="M112.2 238.9h.2M112.2 237.9h.4M112.2 238h.5M112.2 237.8h.4M112.3 239h.3M112.3 239.3h-.9M112.3 238.1h.7M112.3 237.7h.3M112.3 239.1h.5M112.3 238.2h1.1M112.3 239.2h1.4M112.3 237.6h.4"/>
<path d="M112.3 239.3h.2M112.4 238.3h1.2M112.4 237.5h1.2M112.5 238.4h1.2M112.5 237.4h1.1M112.6 239.3h.9M112.7 238.5h1.1M112.7 237.3h.5M112.9 239.4h.3M113.1 238.6h.7M113.2 238.6l.3 .2-.3 .3h-.5l-.5-.4M113.3 239.1h.5"/>
<path d="M113.3 237.6h.4M113.4 238.7h.5M113.4 239h.4M113.5 238.8h.4M113.5 238.9h.3M113.5 237.7h.2M113.6 237.8h.1M113.7 237.9l-.6-.3h-.4l-.1 .2 .1 .2 1.1 .4v.5l-.2 .4-1.3 .1-.1-.7M113.7 237.9l-.1-.6h-.8l-.5 .3-.1 .3 .2 .4 .8 .3M113.7 237.9h.1M99.4 240h1M99.4 240.1h2.2"/>
<path d="M99.5 240.1h2.1M99.5 240.2h2M99.5 240.3h1.9M99.6 240.3h1.8M99.6 240.4h1.8M99.6 240.5h1.7M99.7 240.5h1.6M99.7 240.6h1.6M99.7 240.7h1.5M99.8 240.7h1.4M99.8 240.8h1.4M99.8 240.9h1.4"/>
<path d="M99.9 240.9h1.3M99.9 241h1.3M100 241.1h1.2M100.1 241.2h1.1M100.2 241.3h1M100.2 241.3h1.1M100.3 241.4h1M100.4 241.5h.9M100.6 241.5h.7M100.9 241.6h.1M101.2 240h.5M105 242.6l.3-.3v-2l-.3-.3h1l-.3 .3v2.1l.3 .2"/>
<path d="M105 242.6h1M105.1 240.1h.8M105.2 242.5h.6M105.2 240.2h.6M105.2 242.4h.5M105.3 240.3h.4M105.3 242.3h.4M105.3 242.2h.4M105.3 242.1h.4M105.3 242h.4M105.3 241.9h.4M105.3 241.8h.4"/>
<path d="M105.3 241.7h.4M105.3 241.6h.4M105.3 241.5h.4M105.3 241.4h.4M105.3 241.3h.4M105.3 241.2h.4M105.3 241.1h.4M105.3 241h.4M105.3 240.9h.4M105.3 240.8h.4M105.3 240.7h.4M105.3 240.6h.4"/>
<path d="M105.3 240.5h.4M105.3 240.4h.4M106 242.6h-1M106.1 242.6h.7M106.1 240.6h.6M106.2 240.7h.6M106.3 242.5h.4M106.3 240.8h.6M106.3 242.4h.3M106.3 240.9h.7M106.3 242.3h.3M106.3 242.2h.3"/>
<path d="M106.3 242.1h.3M106.3 242h.3M106.3 241.9h.3M106.3 241.8h.3M106.3 241.7h.3M106.3 241.6h.3M106.3 241.5h.3M106.3 241.4h.3M106.3 241.3h.3M106.3 241.2h.3M106.3 241.1h.8M106.3 241h.8"/>
<path d="M106.6 241.1v1.3l.2 .2M106.6 241.1h.1M106.6 241.1l1.4 1.6v-1.8l.2-.3h-.6l.1 .2 .1 1M106.7 241.2h.5M106.7 241.3h.6M106.8 242.6h-.7M106.8 241.4h.6M106.9 241.5h.6M107 241.6h.6M107.1 241.7h.5M107.1 241.8h.9M107.2 241.9h.8"/>
<path d="M107.3 241.9h.7M107.4 242h.6M107.5 242.1h.5M107.6 242.2h.4M107.6 240.6h.6M107.6 242.3h.4M107.7 240.7h.4M107.7 242.4h.3M107.7 240.8h.3M107.7 241.8l-1-1.2h-.6l.2 .3v1.5l-.2 .2M107.7 241.8h.1M107.7 240.9h.3"/>
<path d="M107.8 241.7h.2M107.8 241.6h.2M107.8 241.5h.2M107.8 241.4h.2M107.8 241.3h.2M107.8 241.2h.2M107.8 241.1h.2M107.8 241h.2M107.8 242.5h.2M107.9 242.6h.1M108.3 242h.1M108.3 242.1h.1"/>
<path d="M108.3 242.2h.3M108.3 241.2h.4M108.3 241.1h.4M108.3 241.3h.5M108.3 242.3h.4M108.3 241h.4M108.4 241.4h.8M108.4 242.4h.6M108.4 240.9h.4M108.4 242.5h1.3M108.4 241.5h1.2M108.4 242.6h.1"/>
<path d="M108.4 240.8h1.3M108.5 241.6h1.2M108.5 240.7h1.2M108.6 241.7h1.2M108.7 242.6h.9M108.7 240.6h.7M108.9 241.8l-.5-.4v-.5l.4-.3h.9l.1 .6-.7-.4-.3 .1-.1 .2 1 .5 .3 .4M108.9 241.8l.6 .1v.4l-.6 .1-.6-.4M108.9 241.8h1M109.2 242.4h.6M109.3 241.9h.6M109.4 240.9h.3"/>
<path d="M109.5 242.3h.4M109.5 241.9h.4M109.5 242.2h.4M109.5 242h.5M109.6 242.1h.3M109.6 240.6h.1M109.6 241h.2M109.7 241.1h.1M109.9 241.1h.1M109.9 241h.2M110 242l-.3 .5-.6 .2-.5-.2-.2 .1-.1-.6M110 240.9h.2"/>
<path d="M110 240.8h1.8M110 240.7h1.7M110.1 240.6h1.6M110.4 242.6h.9M110.6 242.5h.5M110.6 242.4h.5M110.7 240.9h.4M110.7 242.3h.4M110.7 241l-.1-.1h-.3l-.4 .2 .2-.5h1.6l.2 .5-.5-.2h-.3v.1M110.7 241v1.4l-.3 .2M110.7 242.2h.4M110.7 242.1h.4"/>
<path d="M110.7 242h.4M110.7 241.9h.4M110.7 241.8h.4M110.7 241.7h.4M110.7 241.6h.4M110.7 241.5h.4M110.7 241.4h.4M110.7 241.3h.4M110.7 241.2h.4M110.7 241.1h.4M110.7 241h.4M111.1 241v1.4l.2 .2"/>
<path d="M111.3 242.6h-.9M111.6 240.9h.2M111.7 241h.1M111.7 241.1h.1M111.9 242.6l.2-.2v-1.5l-.2-.3 1.5 .1 .3 .2v.4l-.1 .3-.4 .1 .9 .9h-.6l-.5-.7-.5-.1v.6l.2 .2M111.9 242.6h.8M111.9 240.6h1.3M112 240.7h1.5M112 242.5h.6M112.1 240.8h1.5M112.1 242.4h.4M112.1 240.9h.4"/>
<path d="M112.1 242.3h.4M112.1 242.2h.4M112.1 242.1h.4M112.1 242h.4M112.1 241.9h.4M112.1 241.8h1.2M112.1 241.7h1.3M112.1 241.6h1.5M112.1 241.5h.4M112.1 241.4h.4M112.1 241.3h.4M112.1 241.2h.4"/>
<path d="M112.1 241.1h.4M112.1 241h.4M112.7 240.9h-.2v.7M112.7 242.6h-.8M112.9 240.9h.3l.1 .3-.1 .3-.3 .1M112.9 241.9h.6M113 241.9h.5M113.1 242h.5M113.1 242.1h.6M113.1 240.9h.6M113.2 241.5h.5M113.2 242.2h.5"/>
<path d="M113.2 242.3h.6M113.2 241h.5M113.2 241.4h.5M113.3 241.3h.4M113.3 241.1h.5M113.3 241.2h.5M113.3 242.4h.6M113.4 242.5h.6M113.5 242.6h.6M113.9 240.6h.9M114.1 240.7h.5M114.1 240.8h.5"/>
<path d="M114.1 240.9h.5M114.1 241.9h.5M114.1 241.8h.5M114.1 241.7h.5M114.1 241.6h.5M114.1 241.5h.5M114.1 241.4h.5M114.1 241.3h.5M114.1 241.2h.5M114.1 241.1h.5M114.1 241h.5M114.1 242h.5"/>
<path d="M114.1 242.1h.5M114.2 242.2h.4M114.2 242.3h.5M114.3 242.4h.6M114.4 242.5h1.3M114.6 241.9l.1 .4 .4 .1 .4-.1 .1-.4M114.6 241.9v-1l.2-.3h-.9l.2 .3 .1 1.3 .2 .3 .5 .2 .6-.1 .3-.2 .1-.5M114.6 242.6h.9M115.3 242.4h.5M115.4 240.6h.7M115.5 242.3h.3M115.5 240.7h.5"/>
<path d="M115.6 242.2h.3M115.6 242.1h.3M115.6 240.8h.3M115.6 242h.3M115.6 240.9h.3M115.6 241.9v-1l-.2-.3h.7l-.2 .3v1M115.6 241.9h.3M115.6 241.8h.3M115.6 241.7h.3M115.6 241.6h.3M115.6 241.5h.3M115.6 241.4h.3"/>
<path d="M115.6 241.3h.3M115.6 241.2h.3M115.6 241.1h.3M115.6 241h.3M116.2 242.6l.2-.3v-1.4l-.2-.3h.7l.6 1.3 .6-1.3h.7l-.2 .3v1.5l.2 .2M116.2 242.6h.6M116.2 240.6h.7M116.3 240.7h.7M116.3 242.5h.4M116.4 240.8h.6M116.4 242.4h.3M116.4 240.9h.7"/>
<path d="M116.4 242.3h.3M116.4 242.2h.3M116.4 242.1h.3M116.4 242h.3M116.4 241.9h.3M116.4 241.8h.3M116.4 241.7h.3M116.4 241.6h.3M116.4 241.5h.3M116.4 241.4h.3M116.4 241.3h.3M116.4 241.2h.3"/>
<path d="M116.4 241.1h.8M116.4 241h.7M116.7 242.3l.1 .3M116.7 242.3v-1.3l.7 1.7 .8-1.7v1.4l-.2 .2M116.7 241.2h.5M116.8 241.3h.4M116.8 241.4h.5M116.8 242.6h-.6M116.9 241.5h.4M116.9 241.6h.5M116.9 241.7h.5M117 241.8h.4"/>
<path d="M117 241.9h.5M117.1 241.9h.7M117.1 242h.6M117.1 242.1h.6M117.2 242.2h.4M117.2 242.3h.4M117.3 242.4h.3M117.3 242.5h.2M117.4 242.6h.1M117.6 241.9h.2M117.6 241.8h.2M117.6 241.7h.3"/>
<path d="M117.7 241.6h.2M117.7 241.5h.3M117.8 241.4h.2M117.8 241.3h.2M117.8 241.2h.3M117.9 241.1h.7M117.9 241h.7M118 240.9h.6M118 242.6h.8M118 240.8h.6M118 240.7h.7M118.1 240.6h.7"/>
<path d="M118.1 242.5h.6M118.1 242.4h.5M118.2 242.3h.4M118.2 242.2h.4M118.2 242.1h.4M118.2 242h.4M118.2 241.9h.4M118.2 241.8h.4M118.2 241.7h.4M118.2 241.6h.4M118.2 241.5h.4M118.2 241.4h.4"/>
<path d="M118.2 241.3h.4M118.2 241.2h.4M118.8 242.6h-.8M119 242.6h1.6M119 240.6h1.6M119.1 240.7h1.5M119.1 242.5h1.6M119.1 240.8h1.5M119.2 242.4h1.5M119.2 240.9h.4M119.2 242.3h.4M119.2 242.2h.4"/>
<path d="M119.2 242.1h.4M119.2 242h.4M119.2 241.9h.4M119.2 241.8h.4M119.2 241.7h1.3M119.2 241.6h1.3M119.2 241.5h1.3M119.2 241.4h.4M119.2 241.3h.4M119.2 241.2h.4M119.2 241.1h.4M119.2 241h.4"/>
<path d="M119.6 241v.5h.6l.3-.2v.6l-.3-.2h-.6v.7h.8l.4-.3M119.8 240.9l-.2 .1M120.1 240.9l.6 .2M120.3 241.8h.2M120.3 241.4h.2M120.4 240.9h.3M120.6 242.3h.2M120.6 241h.1M120.7 241.1h.1M120.7 241.1l-.2-.5h-1.5l.2 .3v1.4l-.2 .3M120.7 242.2h.1M120.8 242.1h.1"/>
<path d="M120.8 242.1l-.2 .5h-1.6M120.9 242.6h.6M120.9 240.6h.6M121 240.7h.6M121 242.5h.4M121 240.8h.6M121.1 242.4h.2M121.1 240.9h.6M121.1 242.3h.2M121.1 242.2h.2M121.1 242.1h.2M121.1 242h.2"/>
<path d="M121.1 241.9h.2M121.1 241.8h.2M121.1 241.7h.2M121.1 241.6h.2M121.1 241.5h.2M121.1 241.4h.2M121.1 241.3h.2M121.1 241.2h.2M121.1 241.1h.8M121.1 241h.7M121.3 241.1v1.3l.2 .2M121.3 241.1h.1"/>
<path d="M121.3 241.1l1.5 1.6v-1.8l.1-.3h-.6l.2 .3v.9l-1-1.2h-.6l.2 .3v1.4l-.2 .3M121.4 241.2h.6M121.5 241.3h.6M121.5 242.6h-.6M121.6 241.4h.5M121.6 241.5h.6M121.7 241.6h.6M121.8 241.7h.6M121.9 241.8h.9M122 241.9h.8M122.1 241.9h.7M122.1 242h.7"/>
<path d="M122.2 242.1h.6M122.3 242.2h.5M122.3 240.6h.6M122.4 242.3h.4M122.4 240.7h.5M122.5 242.4h.3M122.5 240.8h.3M122.5 240.9h.3M122.5 241.7h.3M122.5 241.6h.3M122.5 241.5h.3M122.5 241.4h.3"/>
<path d="M122.5 241.3h.3M122.5 241.2h.3M122.5 241.1h.3M122.5 241h.3M122.6 242.5h.2M122.6 242.6h.2M123 241.1h.1M123 241h.2M123 240.9h.3M123.1 240.8h1.7M123.1 240.7h1.7M123.1 240.6h1.7"/>
<path d="M123.5 242.6h.9M123.7 242.5h.5M123.7 242.4h.5M123.7 240.9h.5M123.7 241l-.3-.1-.4 .2 .1-.5h1.7l.1 .5-.4-.2h-.3l-.1 .1M123.7 241v1.4l-.2 .2M123.7 242.3h.4M123.7 242.2h.4M123.7 242.1h.4M123.7 242h.4M123.7 241.9h.4M123.7 241.8h.4"/>
<path d="M123.7 241.7h.4M123.7 241.6h.4M123.7 241.5h.4M123.7 241.4h.4M123.7 241.3h.4M123.7 241.2h.4M123.7 241.1h.4M123.7 241h.4M124.1 241l.1 1.4 .2 .2M124.4 242.6h-.9M124.6 240.9h.2M124.7 241h.2"/>
<path d="M124.8 241.1h.1M125 242h.1M125 242.1h.1M125 242.2h.3M125 241.2h.4M125 241.1h.4M125 241.3h.5M125 242.3h.4M125 241h.4M125.1 241.4h.8M125.1 242.4h.6M125.1 240.9h.4"/>
<path d="M125.1 242.5h1.3M125.1 241.5h1.2M125.1 242.6h.1M125.1 240.8h1.3M125.2 241.6h1.2M125.2 240.7h1.2M125.3 241.7h1.2M125.4 242.6h.9M125.4 240.6h.7M125.6 241.8l-.5-.3v-.6l.4-.3h.9l.1 .6-.7-.4-.3 .1-.1 .3 1 .4 .3 .4M125.6 241.8l.6 .1v.4l-.6 .1-.6-.4M125.6 241.8h1"/>
<path d="M125.9 242.4h.6M126 241.9h.6M126.1 240.9h.3M126.2 242.3h.4M126.2 241.9h.4M126.2 242.2h.4M126.2 242h.5M126.3 242.1h.3M126.3 240.6h.1M126.3 241h.2M126.4 241.1h.1M126.7 242l-.3 .5-.6 .2-.5-.2-.2 .1-.1-.6"/>
<circle cx="56.6" cy="117.7" r=".82"/>
</g>
<g fill="#000">
<path d="M78 72.6l1.7-.3v.7zM89 72.3l1.6 .3-1.6 .4zM94.4 62.5l1.7-.3v.6zM98.4 69l1.6-.3v.7zM117.3 68.7l1.7 .3-1.7 .4zM121.3 62.2l1.7 .3-1.7 .3zM166.1 79.4l.3 1.7h-.7zM67.1 78.6h.6l-.3 1.7zM67.4 84.1l.3 1.7h-.6zM76.5 89.9l1.6-.6-1.3 1.2zM121.2 82.5l.2-.1h.3l.1 .3-.1 .2-.3 .1-.2-.2zM135.5 78.7l.6 .4-1.3 1.2z"/>
<path d="M144.1 94.2h.6l-.3 1.6zM149.1 84.9l.3 1.7h-.7zM148.7 94.2h.7l-.3 1.6zM157.1 86.4l.3 1.7h-.6zM67.2 102.3h.6l-.3 1.7zM67.5 109.5l.3 1.6h-.6zM96.7 114.2l1.7-.6-1.3 1.2zM106.2 107.1l1.7-.1-1.5 .8zM144.4 101.3l.3 1.7h-.6zM156.8 114.5h.6l-.3 1.7zM84.3 132.7l1.7-.3v.6zM97.4 126.6l1.6-.4v.7z"/>
<path d="M107 126.2l1.7 .4-1.7 .3zM131.3 132.4l1.7 .3-1.7 .3zM165.7 121.4h.7l-.3 1.7zM66.8 176.5l1.7 .4-1.7 .3zM69.1 176.9l1.7-.4v.7zM72.5 169.6l.3-.1h.2l.2 .3-.2 .2-.2 .1-.3-.2zM74.9 165.1l.6-.3 .6 1.6zM82.3 165.4l.5 .4-1.1 1.2zM129.7 176.5l1.7 .4-1.7 .3zM132.1 176.9l1.6-.4v.7zM138.4 165.1l.6-.3 .6 1.6zM143.7 165.3l.6 .3-.9 1.4z"/>
<path d="M146.7 169.9l.3-.1h.2l.2 .3-.2 .2-.2 .1-.3-.2z"/>
</g>
<path d="M33.2 44.9h149.4v155.2h-149.4z" fill="none" stroke="#000" stroke-width=".36"/>
<path d="M33.2 38h149.2M33.2 233h149.2" fill="none" stroke="#000" stroke-width=".53"/>
<g fill="none" stroke="#007fff" stroke-width=".2">
<path d="M78.1 91.4l.4-.2h11.9l.2 .4v3.1l-.4 .3h-11.9l-.3-.4zM78.3 80.4h12.1l.2 .3v3.2l-.4 .2-11.9-.1-.3-.3v-3zM78.3 85.8h12.1l.2 .4v3.1l-.4 .2h-11.9l-.3-.4v-2.9zM78.3 96.7h12.1l.2 .4v3.1l-.4 .2h-11.9l-.3-.4v-2.9zM94.4 80.7v.9M94.4 82.1v.9M94.4 83.6v.8M94.4 85v.8M94.4 86.4v.8M94.4 87.8v.9M94.4 89.2v.9M94.4 90.7v.8"/>
<path d="M94.4 92.1v.8M94.4 93.5v.8M94.4 94.9v.9M94.4 96.3v.9M94.4 97.7v.9M94.4 99.2v.8M94.8 80.3l-.3 .2M94.8 80.3h.1M95.4 80.3h.9M96.9 80.3h.8M98.3 80.3h.9M99.8 80.3h.9"/>
<path d="M101.2 80.3h.9M102.7 80.3h.9M104.2 80.3h.8M105.6 80.3h.9M107.1 80.3h.9M108.5 80.3h.9M110 80.3h.9M111.5 80.3h.8M112.9 80.3h.9M114.4 80.3h.8M115.8 80.3h.9M117.3 80.3h.9"/>
<path d="M118.7 80.3h.9M120.2 80.3h.9M121.7 80.3h.8M122.8 80.4h.1M122.8 80.4l.1 .1M122.9 80.5h.1M122.9 80.5v.1M122.9 80.6v.1M122.9 80.7h.1M123 80.7h.1M123 81.3v.8M123 82.7v.9"/>
<path d="M123 84.1v.9M123 85.5v.9M123 87v.8M123 88.4v.8M123 89.8v.9M123 91.2v.9M123 92.6v.9M123 94.1v.8M123 95.5v.8M123 96.9v.8M123 98.3v.9M123 99.7v.9"/>
<path d="M126.8 96.9l.3-.2h11.8l.4 .2v.2v2.9l-.2 .4h-.2h-11.8l-.3-.2-.1-.2zM126.8 91.4l.3-.2h11.8l.4 .2v.2v3l-.2 .3-.2 .1h-11.8l-.3-.2-.1-.2zM126.8 80.5l.3-.2h11.8l.4 .2v.2v3l-.2 .3-.2 .1h-11.8l-.3-.2-.1-.2zM126.9 85.8h12.2l.2 .4v3.1l-.4 .2h-12l-.2-.4v-2.9zM78.2 113.2l.3-.2h11.7l.4 .2v.3v2.9l-.2 .4h-.2h-11.9l-.3-.4v-2.9zM78.3 118.6l12.1-.1 .2 .4v3.1l-.4 .3-11.9-.1-.3-.3v-3zM78.3 107.6h12.1l.2 .4v3.2l-.4 .2-11.9-.1-.3-.4v-2.9zM78.3 102.2h12.1l.2 .3v3.1l-.4 .3h-11.9l-.3-.4v-3zM94.4 100.6v.8M94.4 102v.8M94.4 103.4v.9M94.4 104.8v.9"/>
<path d="M94.4 106.3v.8M94.4 107.7v.8M94.4 109.1v.8M94.4 110.5v.9M94.4 111.9v.9M94.4 113.3v.9M94.4 114.8v.8M94.4 116.2v.8M94.4 117.6v.8M94.4 119v.9M123 101.1v.9M123 102.6v.8"/>
<path d="M123 104v.8M123 105.4v.9M123 106.8v.9M123 108.2v.9M123 109.7v.8M123 111.1v.8M123 112.5v.8M123 113.9v.9M123 115.3v.9M123 116.7v.9M123 118.2v.8M123 119.6v.8"/>
<path d="M126.8 107.8l.3-.2h12l.2 .4v3.1l-.4 .3h-11.8l-.3-.2-.1-.3zM126.8 102.3l.3-.2h11.8l.4 .2v.2v3l-.2 .3-.2 .1h-11.8l-.3-.2-.1-.2zM126.9 113.2l.2-.2h11.8l.4 .2v.3v2.9l-.2 .4h-.2h-11.8l-.3-.2-.1-.2v-2.9zM126.9 118.6h12.2l.2 .3v3.2l-.4 .2-12-.1-.2-.3v-3zM94.4 121.9h.1M94.4 120.4v.9M94.4 121.9l.2 .3M94.6 122.2h.1M94.8 122.3h.9M96.3 122.3h.9M97.8 122.3h.8M99.2 122.3h.9"/>
<path d="M100.7 122.3h.8M102.1 122.3h.9M103.6 122.3h.9M105 122.3h.9M106.5 122.3h.9M108 122.3h.8M109.4 122.3h.9M110.9 122.3h.8M112.3 122.3h.9M113.8 122.3h.9M115.2 122.3h.9M116.7 122.3h.9"/>
<path d="M118.2 122.3h.8M119.6 122.3h.9M121.1 122.3h.8M122.6 122.3h-.1M122.6 122.3h.1M122.7 122.2l-.1 .1M122.8 122.2h-.1M122.8 122.2h.1M122.8 122.1v.1M122.9 122.1h-.1M122.9 122.1h.1M123 121v.9"/>
<path d="M69.3 167.2l.4-.2h17.7a.63 .63 0 0 1 .6 .6v4.4a.63 .63 0 0 1-.6 .7h-17.7a.63 .63 0 0 1-.6-.7v-4.4zM131.4 171.2l.1 1.2 .4 .6M131.4 168.2v.9M131.4 169.7v.9M131.9 173v.1M133.3 173.3h.9M133.6 166.4h-1.2l-.7 .5M134.2 166.4h.8M134.7 173.3h.9M135.6 166.4h.9M136.2 173.3h.9M137.1 166.4h.9"/>
<path d="M137.7 173.3h.9M138.6 166.4h.8M139.1 173.3h.9M140 166.4h.9M140.6 173.3h.9M141.5 166.4h.9M142.1 173.3h.9M143 166.4h.8M143.6 173.3h.8M144.4 166.4h.9M145 173.3h.9M145.9 166.4h.9"/>
<path d="M146.5 173.3h.9M147.4 166.4h.9M148 173.3h.8M148.8 166.4h.9M151 166.6l.5 .7 .1 1.2M151.3 172.8l-.7 .5h-1.2M151.6 169.1v.9M151.6 170.6v.9"/>
<circle cx="108.7" cy="95.8" r=".84"/>
<circle cx="108.7" cy="106.7" r=".84"/>
</g>
<path d="M98.6 86.4h20l.3 .2 .1 29.2-.2 .3-20 .1-.4-.2v-29.2zM69 166.6l.7-.2h17.7a1.26 1.26 0 0 1 1.2 1.2v4.4a1.26 1.26 0 0 1-1.2 1.3h-17.7a1.26 1.26 0 0 1-1.2-1.3v-4.4v-.4zM132.2 167.2l.5-.2h17.6a.63 .63 0 0 1 .6 .6v4.4a.63 .63 0 0 1-.6 .7h-17.8l-.4-.3v-.4v-4.4z" fill="none" stroke="#6ef200" stroke-width=".2"/>
<g fill="none" stroke="#007fff" stroke-width=".2" stroke-dasharray=".7 .7" stroke-linecap="butt">
<circle cx="97.4" cy="95.8" r=".84"/>
<circle cx="97.4" cy="84.9" r=".84"/>
<circle cx="108.7" cy="84.9" r=".84"/>
<circle cx="120" cy="95.8" r=".84"/>
<circle cx="120" cy="84.9" r=".84"/>
<circle cx="97.4" cy="117.7" r=".84"/>
<circle cx="97.4" cy="106.7" r=".84"/>
<circle cx="108.7" cy="117.7" r=".84"/>
<circle cx="120" cy="117.7" r=".84"/>
<circle cx="120" cy="106.7" r=".84"/>
</g>
<path d="M27.7 11.6l-.2 .6 .5-.2h.6v.1v2.2l-.2 .4h1l-.2-.4v-2.2v-.1h.5l.5 .2-.1-.6zM29.8 12.4l.2 .3v1.6l-.2 .4h1.9l.1-.6a1.08 1.08 0 0 1-1.3 .2v-.7h.6l.4 .2v-.7l-.4 .2h-.6v-.5l.2-.2a1 1 0 0 1 1 .3l-.1-.5zM31.8 12.4l1 1.1-1 1.2h.9l-.2-.2 .4-.8 .5 .8-.2 .2h1.6l-.2-.2 .1-.5h1l.1 .5-.1 .2h.9l-.2-.4-.8-1.9h-.5l-1 2.1-.8-1.1 .9-1h-.8l.2 .2-.5 .6-.3-.6 .1-.2zM35.2 12.8l.4 1h-.8zM36.8 12.5a.65 .65 0 0 0-.2 .7 .65 .65 0 0 0 .6 .5l.7 .1 .1 .3a.79 .79 0 0 1-.7 .4 .79 .79 0 0 1-.7-.5l.1 .7 .2-.1a.93 .93 0 0 0 1.1 0 .93 .93 0 0 0 .4-.9 1.46 1.46 0 0 0-1.2-.6l-.1-.3a1.09 1.09 0 0 1 1.2 .2l-.2-.6-.1 .1-.6-.2zM28.4 15.2l.2 .4v2.2l-.2 .4h1l-.2-.4v-2.2l.2-.4zM29.6 15.9l.2 .4v1.5l-.2 .4h.8l-.3-.4v-1.3l1.7 1.8v-2l.2-.4h-.8l.2 .2 .1 1.1-1.2-1.3zM32.3 16a.65 .65 0 0 0-.2 .8 .65 .65 0 0 0 .7 .4l.6 .2 .1 .2a.79 .79 0 0 1-.7 .4 .79 .79 0 0 1-.7-.5l.1 .7 .2-.1a.93 .93 0 0 0 1.1 .1 .93 .93 0 0 0 .4-1 1.46 1.46 0 0 0-1.2-.5l-.1-.4a1.09 1.09 0 0 1 1.2 .2l-.2-.6-.1 .1-.6-.1zM34.1 15.9l-.1 .6a.63 .63 0 0 1 .7-.3l.1 1.6-.3 .4h1l-.2-.4v-1.6a.66 .66 0 0 1 .8 .3l-.1-.6zM36.2 15.9l.2 .4v1.5l-.2 .4h.9l-.2-.2v-.7h.5l.1 .2a.79 .79 0 0 0 1.2 .6l-1-.9a.61 .61 0 0 0 .6-.6 .61 .61 0 0 0-.5-.7zM36.9 16.2h.2a.47 .47 0 0 1 .5 .1 .47 .47 0 0 1 .1 .5l-.2 .1-.6 .1zM38.5 15.9l.2 .2a2.27 2.27 0 0 0 .4 2 1.04 1.04 0 0 0 1.7-.7v-1.3l.2-.2h-.8l.2 .4v1.1a.6 .6 0 0 1-.6 .6 .6 .6 0 0 1-.6-.6v-1.1l.3-.4zM41.1 15.9l.2 .4v1.5l-.2 .4h.7l-.2-.4v-1.4l.9 1.9 .8-1.9v1.4l-.2 .4h1l-.3-.4v-1.5l.3-.4h-.8l-.7 1.5-.7-1.5zM44.3 15.9l.2 .4v1.5l-.2 .4h1.9l.1-.6a1.09 1.09 0 0 1-1.3 .2v-.7h.6l.4 .2v-.6l-.4 .2h-.6v-.6l.2-.1a1.01 1.01 0 0 1 1 .3l-.1-.6zM46.4 15.9l.3 .4v1.5l-.3 .4h.8l-.2-.4v-1.3l1.6 1.8v-2l.2-.4h-.7l.2 .2v1.1l-1.2-1.3zM49 15.9l-.1 .6a.63 .63 0 0 1 .8-.3v1.6l-.3 .4h1l-.2-.4v-1.6a.66 .66 0 0 1 .8 .3l-.1-.6zM51.4 16a.65 .65 0 0 0-.2 .8 .65 .65 0 0 0 .6 .4l.6 .2 .2 .2a.79 .79 0 0 1-.8 .4 .79 .79 0 0 1-.6-.5l.1 .7 .2-.1a.93 .93 0 0 0 1 .1 .93 .93 0 0 0 .5-1 1.46 1.46 0 0 0-1.3-.5l-.1-.4a1.09 1.09 0 0 1 1.3 .2l-.2-.6-.2 .1-.5-.1z" fill="#231f20"/>
<path d="M21.1 10.3v2.7h-2v.4l.9 1a.95 .95 0 0 0 .9 .9 .59 .59 0 0 1 .6-.4 .59 .59 0 0 1 .5 .3l.4 .8a1.59 1.59 0 0 0 2.1 1.4 1.61 1.61 0 0 1 1-2.3l1-.3-.1-1.5a1.59 1.59 0 0 1-.4-1.7h-1.4l-.2 .9h.5l-.1 .9h-.5l-.2 .9v.3l.4 .1-.2 .9h-.6a.73 .73 0 0 1-1.1-.7l.3-1.5h-.5l.2-.9h.5l.2-.9h-.5v-1.3zM23.6 11.6l-.6 3.1h.7l.6-3.1zM23.8 10.7l-.1 .6h.7l.1-.6z" fill="#ed1c24"/>
<path d="M19 22.9h177.8M19 262.3h180" fill="none" stroke="#000" stroke-width=".53"/>
<use href="#words"/>
</svg>
